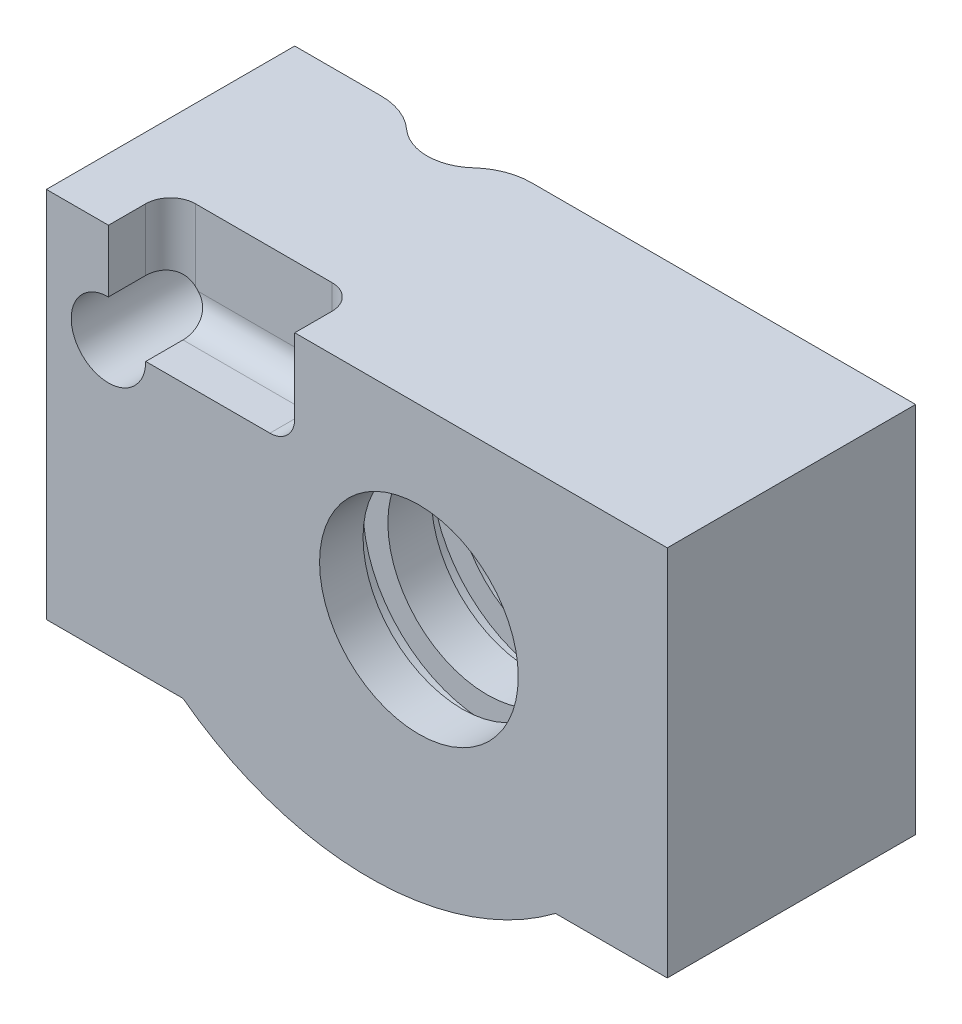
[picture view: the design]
ISO-10303-21;
HEADER;
FILE_DESCRIPTION(('STEP AP214'),'2;1');
FILE_NAME('part.step','',(''),(''),'','','');
FILE_SCHEMA(('AUTOMOTIVE_DESIGN { 1 0 10303 214 1 1 1 1 }'));
ENDSEC;
DATA;
#1=APPLICATION_CONTEXT('core data for automotive mechanical design processes');
#2=APPLICATION_PROTOCOL_DEFINITION('international standard','automotive_design',2000,#1);
#3=PRODUCT_CONTEXT('',#1,'mechanical');
#4=PRODUCT('Part','Part','',(#3));
#5=PRODUCT_RELATED_PRODUCT_CATEGORY('part','',(#4));
#6=PRODUCT_DEFINITION_FORMATION('','',#4);
#7=PRODUCT_DEFINITION_CONTEXT('part definition',#1,'design');
#8=PRODUCT_DEFINITION('design','',#6,#7);
#9=PRODUCT_DEFINITION_SHAPE('','',#8);
#10=(LENGTH_UNIT() NAMED_UNIT(*) SI_UNIT(.MILLI.,.METRE.));
#11=(NAMED_UNIT(*) PLANE_ANGLE_UNIT() SI_UNIT($,.RADIAN.));
#12=(NAMED_UNIT(*) SI_UNIT($,.STERADIAN.) SOLID_ANGLE_UNIT());
#13=UNCERTAINTY_MEASURE_WITH_UNIT(LENGTH_MEASURE(1.E-05),#10,'distance_accuracy_value','');
#14=(GEOMETRIC_REPRESENTATION_CONTEXT(3) GLOBAL_UNCERTAINTY_ASSIGNED_CONTEXT((#13)) GLOBAL_UNIT_ASSIGNED_CONTEXT((#10,
#11,#12)) REPRESENTATION_CONTEXT('',''));
#15=CARTESIAN_POINT('',(0.,0.,0.));
#16=DIRECTION('',(0.,0.,1.));
#17=DIRECTION('',(1.,0.,0.));
#18=AXIS2_PLACEMENT_3D('',#15,#16,#17);
#19=CARTESIAN_POINT('',(-15.,-3.,0.));
#20=DIRECTION('',(0.,0.,1.));
#21=DIRECTION('',(1.,0.,0.));
#22=AXIS2_PLACEMENT_3D('',#19,#20,#21);
#23=CYLINDRICAL_SURFACE('',#22,2.73470224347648);
#24=CARTESIAN_POINT('',(-14.3097315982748,-0.353846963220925,1.29981927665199));
#25=CARTESIAN_POINT('',(-14.2525353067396,-0.368760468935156,1.24781669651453));
#26=CARTESIAN_POINT('',(-14.1944120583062,-0.385909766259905,1.19743520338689));
#27=CARTESIAN_POINT('',(-14.076859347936,-0.425074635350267,1.10011331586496));
#28=CARTESIAN_POINT('',(-14.0174288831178,-0.44709406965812,1.05317569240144));
#29=CARTESIAN_POINT('',(-13.8977510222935,-0.496433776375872,0.962909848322));
#30=CARTESIAN_POINT('',(-13.8375019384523,-0.523767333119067,0.919591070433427));
#31=CARTESIAN_POINT('',(-13.7170788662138,-0.58396219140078,0.836898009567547));
#32=CARTESIAN_POINT('',(-13.6569048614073,-0.616821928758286,0.797522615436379));
#33=CARTESIAN_POINT('',(-13.5370757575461,-0.688431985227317,0.722618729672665));
#34=CARTESIAN_POINT('',(-13.4774254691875,-0.727214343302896,0.687113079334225));
#35=CARTESIAN_POINT('',(-13.3598545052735,-0.810545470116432,0.620250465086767));
#36=CARTESIAN_POINT('',(-13.3019337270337,-0.855093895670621,0.588893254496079));
#37=CARTESIAN_POINT('',(-13.18880539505,-0.949733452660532,0.530336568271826));
#38=CARTESIAN_POINT('',(-13.1335922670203,-0.999812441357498,0.503128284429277));
#39=CARTESIAN_POINT('',(-13.0265936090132,-1.10529180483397,0.452653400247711));
#40=CARTESIAN_POINT('',(-12.9748077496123,-1.16069166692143,0.429386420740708));
#41=CARTESIAN_POINT('',(-12.8344798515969,-1.32416998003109,0.368935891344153));
#42=CARTESIAN_POINT('',(-12.7507455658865,-1.43809325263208,0.336049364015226));
#43=CARTESIAN_POINT('',(-12.6010621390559,-1.67942623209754,0.280873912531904));
#44=CARTESIAN_POINT('',(-12.535127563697,-1.80684686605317,0.2585936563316));
#45=CARTESIAN_POINT('',(-12.4241609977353,-2.07050977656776,0.222859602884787));
#46=CARTESIAN_POINT('',(-12.3789786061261,-2.20668015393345,0.20934199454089));
#47=CARTESIAN_POINT('',(-12.3104350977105,-2.4848632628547,0.189382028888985));
#48=CARTESIAN_POINT('',(-12.2870707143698,-2.6268751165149,0.182938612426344));
#49=CARTESIAN_POINT('',(-12.2626192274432,-2.91648713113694,0.176200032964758));
#50=CARTESIAN_POINT('',(-12.2620956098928,-3.06413874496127,0.17606038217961));
#51=CARTESIAN_POINT('',(-12.2847754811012,-3.35748969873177,0.182302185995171));
#52=CARTESIAN_POINT('',(-12.3079824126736,-3.5031887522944,0.188684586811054));
#53=CARTESIAN_POINT('',(-12.3775659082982,-3.78947891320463,0.208914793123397));
#54=CARTESIAN_POINT('',(-12.4240989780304,-3.93002854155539,0.22281307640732));
#55=CARTESIAN_POINT('',(-12.5386456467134,-4.20080315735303,0.259753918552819));
#56=CARTESIAN_POINT('',(-12.6066570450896,-4.33102920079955,0.282795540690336));
#57=CARTESIAN_POINT('',(-12.7599982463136,-4.57525843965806,0.339612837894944));
#58=CARTESIAN_POINT('',(-12.8450321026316,-4.68948875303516,0.373210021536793));
#59=CARTESIAN_POINT('',(-13.029039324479,-4.90092889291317,0.453056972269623));
#60=CARTESIAN_POINT('',(-13.128003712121,-4.9981495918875,0.499298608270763));
#61=CARTESIAN_POINT('',(-13.332630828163,-5.17165682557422,0.604412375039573));
#62=CARTESIAN_POINT('',(-13.4380995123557,-5.2483550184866,0.662985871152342));
#63=CARTESIAN_POINT('',(-13.6526986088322,-5.38315984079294,0.793529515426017));
#64=CARTESIAN_POINT('',(-13.761832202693,-5.44124982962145,0.865511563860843));
#65=CARTESIAN_POINT('',(-13.9450508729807,-5.52436763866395,0.997554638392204));
#66=CARTESIAN_POINT('',(-14.0194593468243,-5.55405727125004,1.05433974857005));
#67=CARTESIAN_POINT('',(-14.1662950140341,-5.60568092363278,1.17319528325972));
#68=CARTESIAN_POINT('',(-14.2387280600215,-5.62764084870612,1.23524717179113));
#69=CARTESIAN_POINT('',(-14.3097315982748,-5.64615303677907,1.29981927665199));
#70=B_SPLINE_CURVE_WITH_KNOTS('',3,(#24,#25,#26,#27,#28,#29,#30,#31,#32,#33,#34,#35,#36,#37,#38,
#39,#40,#41,#42,#43,#44,#45,#46,#47,#48,#49,#50,#51,#52,#53,#54,#55,#56,#57,#58,#59,#60,#61,#62,
#63,#64,#65,#66,#67,#68,#69),.UNSPECIFIED.,.F.,.F.,(4,2,2,2,2,2,2,2,2,2,2,2,2,2,2,2,2,2,2,2,2,2,
4),(0.,0.236170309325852,0.472528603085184,0.709485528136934,0.946375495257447,1.18459557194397,
1.4228014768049,1.66049440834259,1.89816445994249,2.33134880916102,2.7648865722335,
3.19523067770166,3.62551034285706,4.06639923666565,4.50735210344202,4.95130393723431,
5.39521030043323,5.83198135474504,6.26847219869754,6.69540839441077,7.12272532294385,
7.41687160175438,7.71002247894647),.UNSPECIFIED.);
#71=CARTESIAN_POINT('',(-14.3097315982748,-0.353846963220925,1.29981927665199));
#72=VERTEX_POINT('',#71);
#73=CARTESIAN_POINT('',(-14.3097315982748,-5.64615303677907,1.29981927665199));
#74=VERTEX_POINT('',#73);
#75=EDGE_CURVE('E46',#72,#74,#70,.T.);
#76=ORIENTED_EDGE('',*,*,#75,.T.);
#77=CARTESIAN_POINT('',(-14.3097315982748,-0.353846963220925,1.29981927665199));
#78=CARTESIAN_POINT('',(-14.3670238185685,-0.338899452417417,1.35189784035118));
#79=CARTESIAN_POINT('',(-14.4260795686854,-0.325484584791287,1.40252226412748));
#80=CARTESIAN_POINT('',(-14.5475407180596,-0.302278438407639,1.50061271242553));
#81=CARTESIAN_POINT('',(-14.6099497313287,-0.292491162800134,1.54807520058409));
#82=CARTESIAN_POINT('',(-14.7382636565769,-0.277079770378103,1.63979796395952));
#83=CARTESIAN_POINT('',(-14.8041901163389,-0.271485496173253,1.68403329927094));
#84=CARTESIAN_POINT('',(-14.9387163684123,-0.265155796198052,1.76858375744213));
#85=CARTESIAN_POINT('',(-15.0073152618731,-0.264418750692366,1.80890018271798));
#86=CARTESIAN_POINT('',(-15.1472146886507,-0.26836018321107,1.8856014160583));
#87=CARTESIAN_POINT('',(-15.218531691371,-0.273079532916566,1.92195429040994));
#88=CARTESIAN_POINT('',(-15.362683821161,-0.288485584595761,1.99009257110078));
#89=CARTESIAN_POINT('',(-15.4355187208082,-0.299171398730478,2.02187865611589));
#90=CARTESIAN_POINT('',(-15.581631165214,-0.326836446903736,2.08058365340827));
#91=CARTESIAN_POINT('',(-15.6549059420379,-0.343791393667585,2.10752076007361));
#92=CARTESIAN_POINT('',(-15.8012337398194,-0.384203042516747,2.1566011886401));
#93=CARTESIAN_POINT('',(-15.8742867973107,-0.407658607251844,2.17874534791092));
#94=CARTESIAN_POINT('',(-16.0719221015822,-0.480615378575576,2.23267052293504));
#95=CARTESIAN_POINT('',(-16.1954508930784,-0.536668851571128,2.2597931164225));
#96=CARTESIAN_POINT('',(-16.4343972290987,-0.667678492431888,2.30135074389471));
#97=CARTESIAN_POINT('',(-16.5498061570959,-0.742654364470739,2.31577248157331));
#98=CARTESIAN_POINT('',(-16.7652483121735,-0.907079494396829,2.33420169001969));
#99=CARTESIAN_POINT('',(-16.8656354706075,-0.996034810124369,2.33850470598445));
#100=CARTESIAN_POINT('',(-17.052307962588,-1.18767056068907,2.34042384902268));
#101=CARTESIAN_POINT('',(-17.138593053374,-1.29035123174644,2.33803986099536));
#102=CARTESIAN_POINT('',(-17.3018640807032,-1.51639719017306,2.32917815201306));
#103=CARTESIAN_POINT('',(-17.377423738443,-1.64078044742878,2.32236777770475));
#104=CARTESIAN_POINT('',(-17.5078867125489,-1.89992549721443,2.30784480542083));
#105=CARTESIAN_POINT('',(-17.5627823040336,-2.03469114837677,2.30013187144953));
#106=CARTESIAN_POINT('',(-17.653119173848,-2.31945723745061,2.28627724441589));
#107=CARTESIAN_POINT('',(-17.6872327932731,-2.46988767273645,2.28025402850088));
#108=CARTESIAN_POINT('',(-17.7297161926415,-2.7744344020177,2.27261145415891));
#109=CARTESIAN_POINT('',(-17.7380900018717,-2.92855011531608,2.27099140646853));
#110=CARTESIAN_POINT('',(-17.7288914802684,-3.23424374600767,2.27270573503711));
#111=CARTESIAN_POINT('',(-17.7116082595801,-3.38583076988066,2.27598490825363));
#112=CARTESIAN_POINT('',(-17.6521593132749,-3.68392755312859,2.28626611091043));
#113=CARTESIAN_POINT('',(-17.6099885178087,-3.8304362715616,2.29326889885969));
#114=CARTESIAN_POINT('',(-17.5018278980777,-4.11474201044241,2.30844530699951));
#115=CARTESIAN_POINT('',(-17.4357767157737,-4.25251550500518,2.31662191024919));
#116=CARTESIAN_POINT('',(-17.2815973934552,-4.5152935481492,2.33049846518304));
#117=CARTESIAN_POINT('',(-17.1934659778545,-4.64029619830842,2.33619804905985));
#118=CARTESIAN_POINT('',(-16.9968725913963,-4.87473564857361,2.34088673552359));
#119=CARTESIAN_POINT('',(-16.8882856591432,-4.984069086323,2.33983320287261));
#120=CARTESIAN_POINT('',(-16.6546900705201,-5.18266926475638,2.32645108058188));
#121=CARTESIAN_POINT('',(-16.5296931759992,-5.27195025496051,2.314130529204));
#122=CARTESIAN_POINT('',(-16.2779209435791,-5.42185541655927,2.27586437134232));
#123=CARTESIAN_POINT('',(-16.1519511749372,-5.48410322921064,2.2509864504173));
#124=CARTESIAN_POINT('',(-15.8954077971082,-5.58765255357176,2.18640349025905));
#125=CARTESIAN_POINT('',(-15.7648385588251,-5.62897340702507,2.14671220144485));
#126=CARTESIAN_POINT('',(-15.5132922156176,-5.6890003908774,2.05537025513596));
#127=CARTESIAN_POINT('',(-15.3922670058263,-5.70905410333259,2.00471723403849));
#128=CARTESIAN_POINT('',(-15.1543870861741,-5.73296343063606,1.89089172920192));
#129=CARTESIAN_POINT('',(-15.0375407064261,-5.73678830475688,1.82769572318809));
#130=CARTESIAN_POINT('',(-14.813734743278,-5.730594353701,1.69183596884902));
#131=CARTESIAN_POINT('',(-14.7066064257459,-5.72090162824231,1.61943224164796));
#132=CARTESIAN_POINT('',(-14.5525686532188,-5.69834871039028,1.50419421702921));
#133=CARTESIAN_POINT('',(-14.5024275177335,-5.68952157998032,1.46476339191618));
#134=CARTESIAN_POINT('',(-14.4043866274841,-5.66952032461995,1.38382079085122));
#135=CARTESIAN_POINT('',(-14.3564856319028,-5.65834751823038,1.34231019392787));
#136=CARTESIAN_POINT('',(-14.3097315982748,-5.64615303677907,1.29981927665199));
#137=B_SPLINE_CURVE_WITH_KNOTS('',3,(#77,#78,#79,#80,#81,#82,#83,#84,#85,#86,#87,#88,#89,#90,
#91,#92,#93,#94,#95,#96,#97,#98,#99,#100,#101,#102,#103,#104,#105,#106,#107,#108,#109,#110,#111,
#112,#113,#114,#115,#116,#117,#118,#119,#120,#121,#122,#123,#124,#125,#126,#127,#128,#129,#130,
#131,#132,#133,#134,#135,#136),.UNSPECIFIED.,.F.,.F.,(4,2,2,2,2,2,2,2,2,2,2,2,2,2,2,2,2,2,2,2,2,
2,2,2,2,2,2,2,2,4),(0.,0.236560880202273,0.473382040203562,0.711873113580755,0.950284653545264,
1.19049367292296,1.43066695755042,1.66991937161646,1.90912995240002,2.32182800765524,
2.73495759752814,3.13586206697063,3.53677343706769,3.97196998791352,4.40732906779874,
4.86818550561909,5.32896979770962,5.78460110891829,6.24032526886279,6.69722878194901,
7.15420011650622,7.61405933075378,8.07359072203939,8.49935592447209,8.92472689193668,
9.32115139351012,9.71832646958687,10.106084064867,10.2991756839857,10.4921590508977),.UNSPECIFIED.);
#138=EDGE_CURVE('E52',#72,#74,#137,.T.);
#139=ORIENTED_EDGE('',*,*,#138,.F.);
#140=EDGE_LOOP('',(#76,#139));
#141=FACE_BOUND('',#140,.T.);
#142=CARTESIAN_POINT('',(-15.,-3.,5.));
#143=DIRECTION('',(0.,0.,1.));
#144=DIRECTION('',(1.,0.,0.));
#145=AXIS2_PLACEMENT_3D('',#142,#143,#144);
#146=CIRCLE('',#145,2.73470224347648);
#147=CARTESIAN_POINT('',(-12.2652977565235,-3.,5.));
#148=VERTEX_POINT('',#147);
#149=EDGE_CURVE('E11',#148,#148,#146,.F.);
#150=ORIENTED_EDGE('',*,*,#149,.F.);
#151=EDGE_LOOP('',(#150));
#152=FACE_BOUND('',#151,.T.);
#153=ADVANCED_FACE('F37',(#141,#152),#23,.F.);
#154=CARTESIAN_POINT('',(0.,0.,0.));
#155=DIRECTION('',(0.,0.,-1.));
#156=DIRECTION('',(-1.,0.,0.));
#157=AXIS2_PLACEMENT_3D('',#154,#155,#156);
#158=CYLINDRICAL_SURFACE('',#157,10.);
#159=CARTESIAN_POINT('',(0.,0.,14.5));
#160=DIRECTION('',(0.,0.,-1.));
#161=DIRECTION('',(-1.,0.,0.));
#162=AXIS2_PLACEMENT_3D('',#159,#160,#161);
#163=CIRCLE('',#162,10.);
#164=CARTESIAN_POINT('',(-10.,0.,14.5));
#165=VERTEX_POINT('',#164);
#166=EDGE_CURVE('E366',#165,#165,#163,.T.);
#167=ORIENTED_EDGE('',*,*,#166,.T.);
#168=EDGE_LOOP('',(#167));
#169=FACE_BOUND('',#168,.T.);
#170=CARTESIAN_POINT('',(0.,0.,16.5));
#171=DIRECTION('',(0.,0.,-1.));
#172=DIRECTION('',(-1.,0.,0.));
#173=AXIS2_PLACEMENT_3D('',#170,#171,#172);
#174=CIRCLE('',#173,10.);
#175=CARTESIAN_POINT('',(-10.,0.,16.5));
#176=VERTEX_POINT('',#175);
#177=EDGE_CURVE('E369',#176,#176,#174,.T.);
#178=ORIENTED_EDGE('',*,*,#177,.F.);
#179=EDGE_LOOP('',(#178));
#180=FACE_BOUND('',#179,.T.);
#181=CARTESIAN_POINT('',(0.,0.,16.));
#182=DIRECTION('',(0.,0.,-1.));
#183=DIRECTION('',(-1.,0.,0.));
#184=AXIS2_PLACEMENT_3D('',#181,#182,#183);
#185=CIRCLE('',#184,10.);
#186=CARTESIAN_POINT('',(3.65612152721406,9.30767293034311,16.));
#187=VERTEX_POINT('',#186);
#188=CARTESIAN_POINT('',(-3.65612152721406,9.30767293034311,16.));
#189=VERTEX_POINT('',#188);
#190=EDGE_CURVE('E480',#187,#189,#185,.F.);
#191=ORIENTED_EDGE('',*,*,#190,.F.);
#192=DIRECTION('',(0.,0.,-1.));
#193=VECTOR('',#192,1.);
#194=CARTESIAN_POINT('',(3.65612152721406,9.30767293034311,0.));
#195=LINE('',#194,#193);
#196=CARTESIAN_POINT('',(3.65612152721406,9.30767293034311,15.));
#197=VERTEX_POINT('',#196);
#198=EDGE_CURVE('E477',#197,#187,#195,.F.);
#199=ORIENTED_EDGE('',*,*,#198,.F.);
#200=CARTESIAN_POINT('',(0.,0.,15.));
#201=DIRECTION('',(0.,0.,1.));
#202=DIRECTION('',(1.,0.,0.));
#203=AXIS2_PLACEMENT_3D('',#200,#201,#202);
#204=CIRCLE('',#203,10.);
#205=CARTESIAN_POINT('',(-3.65612152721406,9.30767293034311,15.));
#206=VERTEX_POINT('',#205);
#207=EDGE_CURVE('E470',#206,#197,#204,.F.);
#208=ORIENTED_EDGE('',*,*,#207,.F.);
#209=DIRECTION('',(0.,0.,-1.));
#210=VECTOR('',#209,1.);
#211=CARTESIAN_POINT('',(-3.65612152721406,9.30767293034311,0.));
#212=LINE('',#211,#210);
#213=EDGE_CURVE('E472',#189,#206,#212,.T.);
#214=ORIENTED_EDGE('',*,*,#213,.F.);
#215=EDGE_LOOP('',(#191,#199,#208,#214));
#216=FACE_BOUND('',#215,.T.);
#217=ADVANCED_FACE('F267',(#169,#180,#216),#158,.F.);
#218=CARTESIAN_POINT('',(-4.,5.,0.));
#219=DIRECTION('',(0.,0.,1.));
#220=DIRECTION('',(1.,0.,0.));
#221=AXIS2_PLACEMENT_3D('',#218,#219,#220);
#222=PLANE('',#221);
#223=CARTESIAN_POINT('',(0.,0.,0.));
#224=DIRECTION('',(0.,0.,-1.));
#225=DIRECTION('',(-1.,0.,0.));
#226=AXIS2_PLACEMENT_3D('',#223,#224,#225);
#227=CIRCLE('',#226,8.);
#228=CARTESIAN_POINT('',(-8.,0.,0.));
#229=VERTEX_POINT('',#228);
#230=EDGE_CURVE('E336',#229,#229,#227,.T.);
#231=ORIENTED_EDGE('',*,*,#230,.F.);
#232=EDGE_LOOP('',(#231));
#233=FACE_BOUND('',#232,.T.);
#234=CARTESIAN_POINT('',(-4.,5.,0.));
#235=DIRECTION('',(0.,0.,1.));
#236=DIRECTION('',(1.,0.,0.));
#237=AXIS2_PLACEMENT_3D('',#234,#235,#236);
#238=CIRCLE('',#237,25.);
#239=CARTESIAN_POINT('',(-10.9468960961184,-19.0154249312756,0.));
#240=VERTEX_POINT('',#239);
#241=CARTESIAN_POINT('',(11.,-15.,0.));
#242=VERTEX_POINT('',#241);
#243=EDGE_CURVE('E418',#240,#242,#238,.T.);
#244=ORIENTED_EDGE('',*,*,#243,.F.);
#245=DIRECTION('',(0.,1.,0.));
#246=VECTOR('',#245,1.);
#247=CARTESIAN_POINT('',(-10.9468960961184,5.,0.));
#248=LINE('',#247,#246);
#249=CARTESIAN_POINT('',(-10.9468960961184,15.,0.));
#250=VERTEX_POINT('',#249);
#251=EDGE_CURVE('E395',#240,#250,#248,.T.);
#252=ORIENTED_EDGE('',*,*,#251,.T.);
#253=DIRECTION('',(-1.,0.,0.));
#254=VECTOR('',#253,1.);
#255=CARTESIAN_POINT('',(-30.,15.,0.));
#256=LINE('',#255,#254);
#257=CARTESIAN_POINT('',(20.,15.,0.));
#258=VERTEX_POINT('',#257);
#259=EDGE_CURVE('E412',#258,#250,#256,.T.);
#260=ORIENTED_EDGE('',*,*,#259,.F.);
#261=DIRECTION('',(0.,1.,0.));
#262=VECTOR('',#261,1.);
#263=CARTESIAN_POINT('',(20.,15.,0.));
#264=LINE('',#263,#262);
#265=CARTESIAN_POINT('',(20.,-15.,0.));
#266=VERTEX_POINT('',#265);
#267=EDGE_CURVE('E422',#266,#258,#264,.T.);
#268=ORIENTED_EDGE('',*,*,#267,.F.);
#269=DIRECTION('',(1.,0.,0.));
#270=VECTOR('',#269,1.);
#271=CARTESIAN_POINT('',(11.,-15.,0.));
#272=LINE('',#271,#270);
#273=EDGE_CURVE('E419',#242,#266,#272,.T.);
#274=ORIENTED_EDGE('',*,*,#273,.F.);
#275=EDGE_LOOP('',(#244,#252,#260,#268,#274));
#276=FACE_BOUND('',#275,.T.);
#277=ADVANCED_FACE('F415',(#233,#276),#222,.F.);
#278=CARTESIAN_POINT('',(-30.,15.,20.));
#279=DIRECTION('',(1.,0.,0.));
#280=DIRECTION('',(0.,1.,0.));
#281=AXIS2_PLACEMENT_3D('',#278,#279,#280);
#282=PLANE('',#281);
#283=DIRECTION('',(0.,-1.,0.));
#284=VECTOR('',#283,1.);
#285=CARTESIAN_POINT('',(-30.,15.,0.));
#286=LINE('',#285,#284);
#287=CARTESIAN_POINT('',(-30.,15.,0.));
#288=VERTEX_POINT('',#287);
#289=CARTESIAN_POINT('',(-30.,-15.,0.));
#290=VERTEX_POINT('',#289);
#291=EDGE_CURVE('E242',#288,#290,#286,.T.);
#292=ORIENTED_EDGE('',*,*,#291,.T.);
#293=DIRECTION('',(0.,0.,-1.));
#294=VECTOR('',#293,1.);
#295=CARTESIAN_POINT('',(-30.,-15.,20.));
#296=LINE('',#295,#294);
#297=CARTESIAN_POINT('',(-30.,-15.,20.));
#298=VERTEX_POINT('',#297);
#299=EDGE_CURVE('E391',#298,#290,#296,.T.);
#300=ORIENTED_EDGE('',*,*,#299,.F.);
#301=DIRECTION('',(0.,-1.,0.));
#302=VECTOR('',#301,1.);
#303=CARTESIAN_POINT('',(-30.,15.,20.));
#304=LINE('',#303,#302);
#305=CARTESIAN_POINT('',(-30.,15.,20.));
#306=VERTEX_POINT('',#305);
#307=EDGE_CURVE('E245',#306,#298,#304,.T.);
#308=ORIENTED_EDGE('',*,*,#307,.F.);
#309=DIRECTION('',(0.,0.,-1.));
#310=VECTOR('',#309,1.);
#311=CARTESIAN_POINT('',(-30.,15.,20.));
#312=LINE('',#311,#310);
#313=EDGE_CURVE('E430',#306,#288,#312,.T.);
#314=ORIENTED_EDGE('',*,*,#313,.T.);
#315=EDGE_LOOP('',(#292,#300,#308,#314));
#316=FACE_BOUND('',#315,.T.);
#317=ADVANCED_FACE('F457',(#316),#282,.F.);
#318=CARTESIAN_POINT('',(-30.,-15.,20.));
#319=DIRECTION('',(0.,1.,0.));
#320=DIRECTION('',(0.,0.,1.));
#321=AXIS2_PLACEMENT_3D('',#318,#319,#320);
#322=PLANE('',#321);
#323=DIRECTION('',(1.,0.,0.));
#324=VECTOR('',#323,1.);
#325=CARTESIAN_POINT('',(-30.,-15.,0.));
#326=LINE('',#325,#324);
#327=CARTESIAN_POINT('',(-23.0531039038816,-15.,0.));
#328=VERTEX_POINT('',#327);
#329=EDGE_CURVE('E420',#290,#328,#326,.T.);
#330=ORIENTED_EDGE('',*,*,#329,.T.);
#331=CARTESIAN_POINT('',(-23.0531039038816,-15.,5.));
#332=DIRECTION('',(0.,1.,0.));
#333=DIRECTION('',(0.,0.,1.));
#334=AXIS2_PLACEMENT_3D('',#331,#332,#333);
#335=CIRCLE('',#334,5.);
#336=CARTESIAN_POINT('',(-19.6902684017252,-15.,1.29981927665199));
#337=VERTEX_POINT('',#336);
#338=EDGE_CURVE('E387',#328,#337,#335,.F.);
#339=ORIENTED_EDGE('',*,*,#338,.T.);
#340=CARTESIAN_POINT('',(-17.,-15.,-1.66032530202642));
#341=DIRECTION('',(0.,1.,0.));
#342=DIRECTION('',(0.,0.,1.));
#343=AXIS2_PLACEMENT_3D('',#340,#341,#342);
#344=CIRCLE('',#343,4.);
#345=CARTESIAN_POINT('',(-19.,-15.,1.80377631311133));
#346=VERTEX_POINT('',#345);
#347=EDGE_CURVE('E243',#337,#346,#344,.T.);
#348=ORIENTED_EDGE('',*,*,#347,.T.);
#349=DIRECTION('',(0.,0.,-1.));
#350=VECTOR('',#349,1.);
#351=CARTESIAN_POINT('',(-19.,-15.,20.));
#352=LINE('',#351,#350);
#353=CARTESIAN_POINT('',(-19.,-15.,20.));
#354=VERTEX_POINT('',#353);
#355=EDGE_CURVE('E384',#354,#346,#352,.T.);
#356=ORIENTED_EDGE('',*,*,#355,.F.);
#357=DIRECTION('',(1.,0.,0.));
#358=VECTOR('',#357,1.);
#359=CARTESIAN_POINT('',(-30.,-15.,20.));
#360=LINE('',#359,#358);
#361=EDGE_CURVE('E449',#298,#354,#360,.T.);
#362=ORIENTED_EDGE('',*,*,#361,.F.);
#363=ORIENTED_EDGE('',*,*,#299,.T.);
#364=EDGE_LOOP('',(#330,#339,#348,#356,#362,#363));
#365=FACE_BOUND('',#364,.T.);
#366=ADVANCED_FACE('F230',(#365),#322,.F.);
#367=CARTESIAN_POINT('',(-4.,5.,20.));
#368=DIRECTION('',(0.,0.,-1.));
#369=DIRECTION('',(-1.,0.,0.));
#370=AXIS2_PLACEMENT_3D('',#367,#368,#369);
#371=CYLINDRICAL_SURFACE('',#370,25.);
#372=CARTESIAN_POINT('',(-19.,-15.,1.80377631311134));
#373=CARTESIAN_POINT('',(-18.8766514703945,-15.092531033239,1.87496960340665));
#374=CARTESIAN_POINT('',(-18.7499284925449,-15.1857713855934,1.93937151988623));
#375=CARTESIAN_POINT('',(-18.4905979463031,-15.3727248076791,2.05427814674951));
#376=CARTESIAN_POINT('',(-18.3579886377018,-15.4664380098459,2.10477871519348));
#377=CARTESIAN_POINT('',(-18.0871607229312,-15.6537939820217,2.191738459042));
#378=CARTESIAN_POINT('',(-17.9489177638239,-15.7474341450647,2.22812744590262));
#379=CARTESIAN_POINT('',(-17.6684245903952,-15.9332856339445,2.28602914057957));
#380=CARTESIAN_POINT('',(-17.5261748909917,-16.0254971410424,2.30754375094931));
#381=CARTESIAN_POINT('',(-17.2473858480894,-16.2021780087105,2.33432278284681));
#382=CARTESIAN_POINT('',(-17.1110167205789,-16.2867797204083,2.3404856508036));
#383=CARTESIAN_POINT('',(-16.836738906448,-16.4532948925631,2.33869315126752));
#384=CARTESIAN_POINT('',(-16.6988303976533,-16.5352086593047,2.33073939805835));
#385=CARTESIAN_POINT('',(-16.4229333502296,-16.6955325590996,2.30025769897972));
#386=CARTESIAN_POINT('',(-16.2849454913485,-16.7739492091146,2.27775818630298));
#387=CARTESIAN_POINT('',(-16.010012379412,-16.926794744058,2.21778154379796));
#388=CARTESIAN_POINT('',(-15.873066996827,-17.0012241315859,2.18030630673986));
#389=CARTESIAN_POINT('',(-15.6141808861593,-17.1388866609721,2.09418933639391));
#390=CARTESIAN_POINT('',(-15.4920111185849,-17.202521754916,2.0468783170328));
#391=CARTESIAN_POINT('',(-15.2511730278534,-17.3255320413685,1.93953276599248));
#392=CARTESIAN_POINT('',(-15.1325040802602,-17.3849079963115,1.87950051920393));
#393=CARTESIAN_POINT('',(-14.9000796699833,-17.4990006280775,1.74676245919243));
#394=CARTESIAN_POINT('',(-14.7863247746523,-17.5537167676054,1.67405518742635));
#395=CARTESIAN_POINT('',(-14.5652885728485,-17.6581025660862,1.5162466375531));
#396=CARTESIAN_POINT('',(-14.4580058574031,-17.7077733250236,1.43114807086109));
#397=CARTESIAN_POINT('',(-14.2657805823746,-17.7952476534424,1.26168046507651));
#398=CARTESIAN_POINT('',(-14.1798010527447,-17.8337422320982,1.1788403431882));
#399=CARTESIAN_POINT('',(-14.0148134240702,-17.9065851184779,1.00482544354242));
#400=CARTESIAN_POINT('',(-13.9358040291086,-17.9409341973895,0.913652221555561));
#401=CARTESIAN_POINT('',(-13.7859206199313,-18.0052688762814,0.72384790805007));
#402=CARTESIAN_POINT('',(-13.7150254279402,-18.0352658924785,0.625237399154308));
#403=CARTESIAN_POINT('',(-13.5820659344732,-18.0908900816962,0.421149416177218));
#404=CARTESIAN_POINT('',(-13.519994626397,-18.1165207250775,0.315677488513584));
#405=CARTESIAN_POINT('',(-13.4447966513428,-18.1472717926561,0.173253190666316));
#406=CARTESIAN_POINT('',(-13.4273235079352,-18.1543928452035,0.138971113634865));
#407=CARTESIAN_POINT('',(-13.3933587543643,-18.1681925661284,0.0698820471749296));
#408=CARTESIAN_POINT('',(-13.3768661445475,-18.1748716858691,0.035075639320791));
#409=CARTESIAN_POINT('',(-13.3608627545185,-18.1813340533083,0.));
#410=B_SPLINE_CURVE_WITH_KNOTS('',3,(#372,#373,#374,#375,#376,#377,#378,#379,#380,#381,#382,
#383,#384,#385,#386,#387,#388,#389,#390,#391,#392,#393,#394,#395,#396,#397,#398,#399,#400,#401,
#402,#403,#404,#405,#406,#407,#408,#409),.UNSPECIFIED.,.F.,.F.,(4,2,2,2,2,2,2,2,2,2,2,2,2,2,2,2,
2,2,4),(0.,0.509334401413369,1.01882039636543,1.53080894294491,2.04273198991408,
2.52390640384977,3.00502579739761,3.48520755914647,3.96532865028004,4.40164585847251,
4.83788476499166,5.27417390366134,5.71036771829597,6.08619501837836,6.46195229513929,
6.83670534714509,7.21115914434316,7.32854097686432,7.44580101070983),.UNSPECIFIED.);
#411=CARTESIAN_POINT('',(-14.3097315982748,-17.7751933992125,1.299819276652));
#412=VERTEX_POINT('',#411);
#413=EDGE_CURVE('E235',#346,#412,#410,.T.);
#414=ORIENTED_EDGE('',*,*,#413,.T.);
#415=CARTESIAN_POINT('',(-14.3097315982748,-17.7751933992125,1.29981927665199));
#416=CARTESIAN_POINT('',(-14.1978751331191,-17.8258366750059,1.19815632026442));
#417=CARTESIAN_POINT('',(-14.0816547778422,-17.8774454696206,1.10179760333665));
#418=CARTESIAN_POINT('',(-13.8413583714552,-17.9818343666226,0.920201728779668));
#419=CARTESIAN_POINT('',(-13.7172839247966,-18.0346142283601,0.834962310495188));
#420=CARTESIAN_POINT('',(-13.4657670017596,-18.1390857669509,0.678356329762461));
#421=CARTESIAN_POINT('',(-13.338523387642,-18.1907652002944,0.606661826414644));
#422=CARTESIAN_POINT('',(-13.0781893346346,-18.2939063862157,0.474639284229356));
#423=CARTESIAN_POINT('',(-12.9450989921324,-18.3453681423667,0.414311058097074));
#424=CARTESIAN_POINT('',(-12.6652657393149,-18.4507335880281,0.301984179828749));
#425=CARTESIAN_POINT('',(-12.5181924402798,-18.5045849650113,0.250757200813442));
#426=CARTESIAN_POINT('',(-12.2193957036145,-18.6107325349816,0.162125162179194));
#427=CARTESIAN_POINT('',(-12.0676723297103,-18.6630287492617,0.12471991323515));
#428=CARTESIAN_POINT('',(-11.7558575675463,-18.7670874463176,0.0632397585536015));
#429=CARTESIAN_POINT('',(-11.5956530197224,-18.8187815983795,0.0396203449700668));
#430=CARTESIAN_POINT('',(-11.2727716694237,-18.9193577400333,0.00798840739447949));
#431=CARTESIAN_POINT('',(-11.1100938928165,-18.9682385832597,-1.77976235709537E-05));
#432=CARTESIAN_POINT('',(-10.9468960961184,-19.0154249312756,0.));
#433=B_SPLINE_CURVE_WITH_KNOTS('',3,(#415,#416,#417,#418,#419,#420,#421,#422,#423,#424,#425,
#426,#427,#428,#429,#430,#431,#432),.UNSPECIFIED.,.F.,.F.,(4,2,2,2,2,2,2,2,4),(0.,
0.478065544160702,0.956033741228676,1.42028420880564,1.8845270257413,2.37823435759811,
2.87193492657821,3.381138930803,3.89054897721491),.UNSPECIFIED.);
#434=EDGE_CURVE('E205',#412,#240,#433,.T.);
#435=ORIENTED_EDGE('',*,*,#434,.T.);
#436=ORIENTED_EDGE('',*,*,#243,.T.);
#437=DIRECTION('',(0.,0.,-1.));
#438=VECTOR('',#437,1.);
#439=CARTESIAN_POINT('',(11.,-15.,20.));
#440=LINE('',#439,#438);
#441=CARTESIAN_POINT('',(11.,-15.,20.));
#442=VERTEX_POINT('',#441);
#443=EDGE_CURVE('E392',#442,#242,#440,.T.);
#444=ORIENTED_EDGE('',*,*,#443,.F.);
#445=CARTESIAN_POINT('',(-4.,5.,20.));
#446=DIRECTION('',(0.,0.,1.));
#447=DIRECTION('',(1.,0.,0.));
#448=AXIS2_PLACEMENT_3D('',#445,#446,#447);
#449=CIRCLE('',#448,25.);
#450=EDGE_CURVE('E390',#354,#442,#449,.T.);
#451=ORIENTED_EDGE('',*,*,#450,.F.);
#452=ORIENTED_EDGE('',*,*,#355,.T.);
#453=EDGE_LOOP('',(#414,#435,#436,#444,#451,#452));
#454=FACE_BOUND('',#453,.T.);
#455=ADVANCED_FACE('F224',(#454),#371,.T.);
#456=CARTESIAN_POINT('',(11.,-15.,20.));
#457=DIRECTION('',(0.,1.,0.));
#458=DIRECTION('',(0.,0.,1.));
#459=AXIS2_PLACEMENT_3D('',#456,#457,#458);
#460=PLANE('',#459);
#461=ORIENTED_EDGE('',*,*,#273,.T.);
#462=DIRECTION('',(0.,0.,-1.));
#463=VECTOR('',#462,1.);
#464=CARTESIAN_POINT('',(20.,-15.,20.));
#465=LINE('',#464,#463);
#466=CARTESIAN_POINT('',(20.,-15.,20.));
#467=VERTEX_POINT('',#466);
#468=EDGE_CURVE('E398',#467,#266,#465,.T.);
#469=ORIENTED_EDGE('',*,*,#468,.F.);
#470=DIRECTION('',(1.,0.,0.));
#471=VECTOR('',#470,1.);
#472=CARTESIAN_POINT('',(11.,-15.,20.));
#473=LINE('',#472,#471);
#474=EDGE_CURVE('E444',#442,#467,#473,.T.);
#475=ORIENTED_EDGE('',*,*,#474,.F.);
#476=ORIENTED_EDGE('',*,*,#443,.T.);
#477=EDGE_LOOP('',(#461,#469,#475,#476));
#478=FACE_BOUND('',#477,.T.);
#479=ADVANCED_FACE('F229',(#478),#460,.F.);
#480=CARTESIAN_POINT('',(20.,15.,20.));
#481=DIRECTION('',(-1.,0.,0.));
#482=DIRECTION('',(0.,-1.,0.));
#483=AXIS2_PLACEMENT_3D('',#480,#481,#482);
#484=PLANE('',#483);
#485=ORIENTED_EDGE('',*,*,#267,.T.);
#486=DIRECTION('',(0.,0.,-1.));
#487=VECTOR('',#486,1.);
#488=CARTESIAN_POINT('',(20.,15.,20.));
#489=LINE('',#488,#487);
#490=CARTESIAN_POINT('',(20.,15.,20.));
#491=VERTEX_POINT('',#490);
#492=EDGE_CURVE('E433',#491,#258,#489,.T.);
#493=ORIENTED_EDGE('',*,*,#492,.F.);
#494=DIRECTION('',(0.,1.,0.));
#495=VECTOR('',#494,1.);
#496=CARTESIAN_POINT('',(20.,15.,20.));
#497=LINE('',#496,#495);
#498=EDGE_CURVE('E441',#467,#491,#497,.T.);
#499=ORIENTED_EDGE('',*,*,#498,.F.);
#500=ORIENTED_EDGE('',*,*,#468,.T.);
#501=EDGE_LOOP('',(#485,#493,#499,#500));
#502=FACE_BOUND('',#501,.T.);
#503=ADVANCED_FACE('F439',(#502),#484,.F.);
#504=CARTESIAN_POINT('',(-30.,15.,20.));
#505=DIRECTION('',(0.,-1.,0.));
#506=DIRECTION('',(0.,0.,-1.));
#507=AXIS2_PLACEMENT_3D('',#504,#505,#506);
#508=PLANE('',#507);
#509=DIRECTION('',(-1.,0.,0.));
#510=VECTOR('',#509,1.);
#511=CARTESIAN_POINT('',(-30.,15.,20.));
#512=LINE('',#511,#510);
#513=CARTESIAN_POINT('',(-25.,15.,20.));
#514=VERTEX_POINT('',#513);
#515=EDGE_CURVE('E447',#514,#306,#512,.T.);
#516=ORIENTED_EDGE('',*,*,#515,.F.);
#517=DIRECTION('',(0.,0.,1.));
#518=VECTOR('',#517,1.);
#519=CARTESIAN_POINT('',(-25.,15.,15.));
#520=LINE('',#519,#518);
#521=CARTESIAN_POINT('',(-25.,15.,17.));
#522=VERTEX_POINT('',#521);
#523=EDGE_CURVE('E327',#522,#514,#520,.T.);
#524=ORIENTED_EDGE('',*,*,#523,.F.);
#525=CARTESIAN_POINT('',(-23.,15.,17.));
#526=DIRECTION('',(0.,-1.,0.));
#527=DIRECTION('',(0.,0.,-1.));
#528=AXIS2_PLACEMENT_3D('',#525,#526,#527);
#529=CIRCLE('',#528,2.);
#530=CARTESIAN_POINT('',(-23.,15.,15.));
#531=VERTEX_POINT('',#530);
#532=EDGE_CURVE('E505',#522,#531,#529,.T.);
#533=ORIENTED_EDGE('',*,*,#532,.T.);
#534=DIRECTION('',(-1.,0.,0.));
#535=VECTOR('',#534,1.);
#536=CARTESIAN_POINT('',(-25.,15.,15.));
#537=LINE('',#536,#535);
#538=CARTESIAN_POINT('',(-12.,15.,15.));
#539=VERTEX_POINT('',#538);
#540=EDGE_CURVE('E315',#539,#531,#537,.T.);
#541=ORIENTED_EDGE('',*,*,#540,.F.);
#542=CARTESIAN_POINT('',(-12.,15.,17.));
#543=DIRECTION('',(0.,-1.,0.));
#544=DIRECTION('',(0.,0.,-1.));
#545=AXIS2_PLACEMENT_3D('',#542,#543,#544);
#546=CIRCLE('',#545,2.);
#547=CARTESIAN_POINT('',(-10.,15.,17.));
#548=VERTEX_POINT('',#547);
#549=EDGE_CURVE('E282',#539,#548,#546,.T.);
#550=ORIENTED_EDGE('',*,*,#549,.T.);
#551=DIRECTION('',(0.,0.,1.));
#552=VECTOR('',#551,1.);
#553=CARTESIAN_POINT('',(-10.,15.,15.));
#554=LINE('',#553,#552);
#555=CARTESIAN_POINT('',(-10.,15.,20.));
#556=VERTEX_POINT('',#555);
#557=EDGE_CURVE('E318',#548,#556,#554,.T.);
#558=ORIENTED_EDGE('',*,*,#557,.T.);
#559=EDGE_CURVE('E434',#491,#556,#512,.T.);
#560=ORIENTED_EDGE('',*,*,#559,.F.);
#561=ORIENTED_EDGE('',*,*,#492,.T.);
#562=ORIENTED_EDGE('',*,*,#259,.T.);
#563=CARTESIAN_POINT('',(-10.9468960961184,15.,5.));
#564=DIRECTION('',(0.,-1.,0.));
#565=DIRECTION('',(0.,0.,-1.));
#566=AXIS2_PLACEMENT_3D('',#563,#564,#565);
#567=CIRCLE('',#566,5.);
#568=CARTESIAN_POINT('',(-14.3097315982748,15.,1.29981927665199));
#569=VERTEX_POINT('',#568);
#570=EDGE_CURVE('E208',#250,#569,#567,.F.);
#571=ORIENTED_EDGE('',*,*,#570,.T.);
#572=CARTESIAN_POINT('',(-17.,15.,-1.66032530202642));
#573=DIRECTION('',(0.,1.,0.));
#574=DIRECTION('',(0.,0.,1.));
#575=AXIS2_PLACEMENT_3D('',#572,#573,#574);
#576=CIRCLE('',#575,4.);
#577=CARTESIAN_POINT('',(-19.6902684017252,15.,1.29981927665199));
#578=VERTEX_POINT('',#577);
#579=EDGE_CURVE('E377',#578,#569,#576,.T.);
#580=ORIENTED_EDGE('',*,*,#579,.F.);
#581=CARTESIAN_POINT('',(-23.0531039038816,15.,5.));
#582=DIRECTION('',(0.,-1.,0.));
#583=DIRECTION('',(0.,0.,-1.));
#584=AXIS2_PLACEMENT_3D('',#581,#582,#583);
#585=CIRCLE('',#584,5.);
#586=CARTESIAN_POINT('',(-23.0531039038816,15.,0.));
#587=VERTEX_POINT('',#586);
#588=EDGE_CURVE('E404',#578,#587,#585,.F.);
#589=ORIENTED_EDGE('',*,*,#588,.T.);
#590=EDGE_CURVE('E428',#587,#288,#256,.T.);
#591=ORIENTED_EDGE('',*,*,#590,.T.);
#592=ORIENTED_EDGE('',*,*,#313,.F.);
#593=EDGE_LOOP('',(#516,#524,#533,#541,#550,#558,#560,#561,#562,#571,#580,#589,#591,#592));
#594=FACE_BOUND('',#593,.T.);
#595=ADVANCED_FACE('F408',(#594),#508,.F.);
#596=CARTESIAN_POINT('',(-4.,5.,20.));
#597=DIRECTION('',(0.,0.,1.));
#598=DIRECTION('',(1.,0.,0.));
#599=AXIS2_PLACEMENT_3D('',#596,#597,#598);
#600=PLANE('',#599);
#601=CARTESIAN_POINT('',(-25.,7.,20.));
#602=DIRECTION('',(0.,0.,1.));
#603=DIRECTION('',(1.,0.,0.));
#604=AXIS2_PLACEMENT_3D('',#601,#602,#603);
#605=CIRCLE('',#604,3.);
#606=CARTESIAN_POINT('',(-25.,10.,20.));
#607=VERTEX_POINT('',#606);
#608=CARTESIAN_POINT('',(-22.,7.,20.));
#609=VERTEX_POINT('',#608);
#610=EDGE_CURVE('E200',#607,#609,#605,.T.);
#611=ORIENTED_EDGE('',*,*,#610,.F.);
#612=DIRECTION('',(0.,-1.,0.));
#613=VECTOR('',#612,1.);
#614=CARTESIAN_POINT('',(-25.,15.,20.));
#615=LINE('',#614,#613);
#616=EDGE_CURVE('E320',#514,#607,#615,.T.);
#617=ORIENTED_EDGE('',*,*,#616,.F.);
#618=ORIENTED_EDGE('',*,*,#515,.T.);
#619=ORIENTED_EDGE('',*,*,#307,.T.);
#620=ORIENTED_EDGE('',*,*,#361,.T.);
#621=ORIENTED_EDGE('',*,*,#450,.T.);
#622=ORIENTED_EDGE('',*,*,#474,.T.);
#623=ORIENTED_EDGE('',*,*,#498,.T.);
#624=ORIENTED_EDGE('',*,*,#559,.T.);
#625=DIRECTION('',(0.,1.,0.));
#626=VECTOR('',#625,1.);
#627=CARTESIAN_POINT('',(-10.,15.,20.));
#628=LINE('',#627,#626);
#629=CARTESIAN_POINT('',(-10.,9.,20.));
#630=VERTEX_POINT('',#629);
#631=EDGE_CURVE('E319',#630,#556,#628,.T.);
#632=ORIENTED_EDGE('',*,*,#631,.F.);
#633=CARTESIAN_POINT('',(-12.,9.,20.));
#634=DIRECTION('',(0.,0.,1.));
#635=DIRECTION('',(1.,0.,0.));
#636=AXIS2_PLACEMENT_3D('',#633,#634,#635);
#637=CIRCLE('',#636,2.);
#638=CARTESIAN_POINT('',(-12.,7.,20.));
#639=VERTEX_POINT('',#638);
#640=EDGE_CURVE('E502',#630,#639,#637,.F.);
#641=ORIENTED_EDGE('',*,*,#640,.T.);
#642=DIRECTION('',(1.,0.,0.));
#643=VECTOR('',#642,1.);
#644=CARTESIAN_POINT('',(-25.,7.,20.));
#645=LINE('',#644,#643);
#646=EDGE_CURVE('E323',#609,#639,#645,.T.);
#647=ORIENTED_EDGE('',*,*,#646,.F.);
#648=EDGE_LOOP('',(#611,#617,#618,#619,#620,#621,#622,#623,#624,#632,#641,#647));
#649=FACE_BOUND('',#648,.T.);
#650=CARTESIAN_POINT('',(0.,0.,20.));
#651=DIRECTION('',(0.,0.,-1.));
#652=DIRECTION('',(-1.,0.,0.));
#653=AXIS2_PLACEMENT_3D('',#650,#651,#652);
#654=CIRCLE('',#653,8.);
#655=CARTESIAN_POINT('',(-8.,0.,20.));
#656=VERTEX_POINT('',#655);
#657=EDGE_CURVE('E375',#656,#656,#654,.T.);
#658=ORIENTED_EDGE('',*,*,#657,.T.);
#659=EDGE_LOOP('',(#658));
#660=FACE_BOUND('',#659,.T.);
#661=ADVANCED_FACE('F254',(#649,#660),#600,.T.);
#662=DIRECTION('',(0.,1.,0.));
#663=VECTOR('',#662,1.);
#664=CARTESIAN_POINT('',(-23.0531039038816,5.,0.));
#665=LINE('',#664,#663);
#666=CARTESIAN_POINT('',(-23.0531039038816,9.28245385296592,0.));
#667=VERTEX_POINT('',#666);
#668=EDGE_CURVE('E219',#587,#667,#665,.F.);
#669=ORIENTED_EDGE('',*,*,#668,.T.);
#670=CARTESIAN_POINT('',(-25.,7.,0.));
#671=DIRECTION('',(0.,0.,1.));
#672=DIRECTION('',(1.,0.,0.));
#673=AXIS2_PLACEMENT_3D('',#670,#671,#672);
#674=CIRCLE('',#673,3.);
#675=CARTESIAN_POINT('',(-23.0531039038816,4.71754614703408,0.));
#676=VERTEX_POINT('',#675);
#677=EDGE_CURVE('E59',#667,#676,#674,.T.);
#678=ORIENTED_EDGE('',*,*,#677,.T.);
#679=EDGE_CURVE('E218',#676,#328,#665,.F.);
#680=ORIENTED_EDGE('',*,*,#679,.T.);
#681=ORIENTED_EDGE('',*,*,#329,.F.);
#682=ORIENTED_EDGE('',*,*,#291,.F.);
#683=ORIENTED_EDGE('',*,*,#590,.F.);
#684=EDGE_LOOP('',(#669,#678,#680,#681,#682,#683));
#685=FACE_BOUND('',#684,.T.);
#686=ADVANCED_FACE('F251',(#685),#222,.F.);
#687=CARTESIAN_POINT('',(-17.,-20.,-1.66032530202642));
#688=DIRECTION('',(0.,1.,0.));
#689=DIRECTION('',(0.,0.,1.));
#690=AXIS2_PLACEMENT_3D('',#687,#688,#689);
#691=CYLINDRICAL_SURFACE('',#690,4.);
#692=DIRECTION('',(0.,1.,0.));
#693=VECTOR('',#692,1.);
#694=CARTESIAN_POINT('',(-14.3097315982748,-20.,1.29981927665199));
#695=LINE('',#694,#693);
#696=EDGE_CURVE('E199',#569,#72,#695,.F.);
#697=ORIENTED_EDGE('',*,*,#696,.T.);
#698=ORIENTED_EDGE('',*,*,#138,.T.);
#699=EDGE_CURVE('E196',#74,#412,#695,.F.);
#700=ORIENTED_EDGE('',*,*,#699,.T.);
#701=ORIENTED_EDGE('',*,*,#413,.F.);
#702=ORIENTED_EDGE('',*,*,#347,.F.);
#703=DIRECTION('',(0.,1.,0.));
#704=VECTOR('',#703,1.);
#705=CARTESIAN_POINT('',(-19.6902684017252,-20.,1.29981927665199));
#706=LINE('',#705,#704);
#707=EDGE_CURVE('E206',#337,#578,#706,.T.);
#708=ORIENTED_EDGE('',*,*,#707,.T.);
#709=ORIENTED_EDGE('',*,*,#579,.T.);
#710=EDGE_LOOP('',(#697,#698,#700,#701,#702,#708,#709));
#711=FACE_BOUND('',#710,.T.);
#712=ADVANCED_FACE('F194',(#711),#691,.F.);
#713=CARTESIAN_POINT('',(-10.9468960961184,-20.,5.));
#714=DIRECTION('',(0.,1.,0.));
#715=DIRECTION('',(0.,0.,1.));
#716=AXIS2_PLACEMENT_3D('',#713,#714,#715);
#717=CYLINDRICAL_SURFACE('',#716,5.);
#718=ORIENTED_EDGE('',*,*,#75,.F.);
#719=ORIENTED_EDGE('',*,*,#696,.F.);
#720=ORIENTED_EDGE('',*,*,#570,.F.);
#721=ORIENTED_EDGE('',*,*,#251,.F.);
#722=ORIENTED_EDGE('',*,*,#434,.F.);
#723=ORIENTED_EDGE('',*,*,#699,.F.);
#724=EDGE_LOOP('',(#718,#719,#720,#721,#722,#723));
#725=FACE_BOUND('',#724,.T.);
#726=ADVANCED_FACE('F203',(#725),#717,.T.);
#727=CARTESIAN_POINT('',(-23.0531039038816,-20.,5.));
#728=DIRECTION('',(0.,1.,0.));
#729=DIRECTION('',(0.,0.,1.));
#730=AXIS2_PLACEMENT_3D('',#727,#728,#729);
#731=CYLINDRICAL_SURFACE('',#730,5.);
#732=CARTESIAN_POINT('',(-23.0531039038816,9.28245385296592,0.));
#733=CARTESIAN_POINT('',(-22.9893216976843,9.22806071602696,-1.68794127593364E-06));
#734=CARTESIAN_POINT('',(-22.9278456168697,9.17099290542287,0.00122046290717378));
#735=CARTESIAN_POINT('',(-22.8099310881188,9.05197436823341,0.00556891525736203));
#736=CARTESIAN_POINT('',(-22.7534908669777,8.99002537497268,0.00869454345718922));
#737=CARTESIAN_POINT('',(-22.6460712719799,8.86172377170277,0.0163041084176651));
#738=CARTESIAN_POINT('',(-22.5950875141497,8.79537476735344,0.0207869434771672));
#739=CARTESIAN_POINT('',(-22.4988663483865,8.65871140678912,0.0305778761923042));
#740=CARTESIAN_POINT('',(-22.4536293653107,8.58839675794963,0.0358860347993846));
#741=CARTESIAN_POINT('',(-22.3270489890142,8.37227492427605,0.0522620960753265));
#742=CARTESIAN_POINT('',(-22.2546797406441,8.22110257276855,0.0637955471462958));
#743=CARTESIAN_POINT('',(-22.1360800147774,7.90878565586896,0.0844412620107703));
#744=CARTESIAN_POINT('',(-22.0898442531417,7.74764311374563,0.0935540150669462));
#745=CARTESIAN_POINT('',(-22.0245197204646,7.41824290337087,0.106825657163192));
#746=CARTESIAN_POINT('',(-22.0056695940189,7.24993569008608,0.110940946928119));
#747=CARTESIAN_POINT('',(-21.996530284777,6.91252570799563,0.112906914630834));
#748=CARTESIAN_POINT('',(-22.0062384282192,6.74342301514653,0.110758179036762));
#749=CARTESIAN_POINT('',(-22.0533635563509,6.41296360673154,0.100911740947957));
#750=CARTESIAN_POINT('',(-22.0901922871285,6.25151875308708,0.0933319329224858));
#751=CARTESIAN_POINT('',(-22.1898174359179,5.93693184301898,0.0748319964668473));
#752=CARTESIAN_POINT('',(-22.2526332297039,5.78379607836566,0.0639093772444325));
#753=CARTESIAN_POINT('',(-22.4038144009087,5.48738416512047,0.0417388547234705));
#754=CARTESIAN_POINT('',(-22.4926047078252,5.34432553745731,0.0304885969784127));
#755=CARTESIAN_POINT('',(-22.6928882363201,5.07509876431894,0.0119873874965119));
#756=CARTESIAN_POINT('',(-22.8043244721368,4.94888951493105,0.00472656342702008));
#757=CARTESIAN_POINT('',(-22.9461120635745,4.81313568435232,0.00110156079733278));
#758=CARTESIAN_POINT('',(-22.9671353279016,4.79358003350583,0.000693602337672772));
#759=CARTESIAN_POINT('',(-23.0097167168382,4.75509650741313,0.000143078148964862));
#760=CARTESIAN_POINT('',(-23.0312743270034,4.73616806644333,2.6649178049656E-07));
#761=CARTESIAN_POINT('',(-23.0531039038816,4.71754614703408,0.));
#762=B_SPLINE_CURVE_WITH_KNOTS('',3,(#732,#733,#734,#735,#736,#737,#738,#739,#740,#741,#742,
#743,#744,#745,#746,#747,#748,#749,#750,#751,#752,#753,#754,#755,#756,#757,#758,#759,#760,#761),
.UNSPECIFIED.,.F.,.F.,(4,2,2,2,2,2,2,2,2,2,2,2,2,2,4),(0.,0.251366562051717,0.502644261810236,
0.753718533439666,1.00481135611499,1.50627281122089,2.00763283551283,2.51333614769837,
3.01899211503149,3.51399177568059,4.00936117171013,4.51333695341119,5.0160599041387,
5.10220060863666,5.18826137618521),.UNSPECIFIED.);
#763=EDGE_CURVE('E306',#667,#676,#762,.T.);
#764=ORIENTED_EDGE('',*,*,#763,.F.);
#765=ORIENTED_EDGE('',*,*,#668,.F.);
#766=ORIENTED_EDGE('',*,*,#588,.F.);
#767=ORIENTED_EDGE('',*,*,#707,.F.);
#768=ORIENTED_EDGE('',*,*,#338,.F.);
#769=ORIENTED_EDGE('',*,*,#679,.F.);
#770=EDGE_LOOP('',(#764,#765,#766,#767,#768,#769));
#771=FACE_BOUND('',#770,.T.);
#772=ADVANCED_FACE('F301',(#771),#731,.T.);
#773=CARTESIAN_POINT('',(0.,0.,0.));
#774=DIRECTION('',(0.,0.,-1.));
#775=DIRECTION('',(-1.,0.,0.));
#776=AXIS2_PLACEMENT_3D('',#773,#774,#775);
#777=CYLINDRICAL_SURFACE('',#776,8.);
#778=ORIENTED_EDGE('',*,*,#657,.F.);
#779=EDGE_LOOP('',(#778));
#780=FACE_BOUND('',#779,.T.);
#781=CARTESIAN_POINT('',(0.,0.,16.5));
#782=DIRECTION('',(0.,0.,-1.));
#783=DIRECTION('',(-1.,0.,0.));
#784=AXIS2_PLACEMENT_3D('',#781,#782,#783);
#785=CIRCLE('',#784,8.);
#786=CARTESIAN_POINT('',(-8.,0.,16.5));
#787=VERTEX_POINT('',#786);
#788=EDGE_CURVE('E372',#787,#787,#785,.T.);
#789=ORIENTED_EDGE('',*,*,#788,.T.);
#790=EDGE_LOOP('',(#789));
#791=FACE_BOUND('',#790,.T.);
#792=ADVANCED_FACE('F252',(#780,#791),#777,.F.);
#793=CARTESIAN_POINT('',(-10.,0.,16.5));
#794=DIRECTION('',(0.,0.,1.));
#795=DIRECTION('',(1.,0.,0.));
#796=AXIS2_PLACEMENT_3D('',#793,#794,#795);
#797=PLANE('',#796);
#798=ORIENTED_EDGE('',*,*,#788,.F.);
#799=EDGE_LOOP('',(#798));
#800=FACE_BOUND('',#799,.T.);
#801=ORIENTED_EDGE('',*,*,#177,.T.);
#802=EDGE_LOOP('',(#801));
#803=FACE_BOUND('',#802,.T.);
#804=ADVANCED_FACE('F647',(#800,#803),#797,.F.);
#805=CARTESIAN_POINT('',(-10.,0.,14.5));
#806=DIRECTION('',(0.,0.,-1.));
#807=DIRECTION('',(-1.,0.,0.));
#808=AXIS2_PLACEMENT_3D('',#805,#806,#807);
#809=PLANE('',#808);
#810=ORIENTED_EDGE('',*,*,#166,.F.);
#811=EDGE_LOOP('',(#810));
#812=FACE_BOUND('',#811,.T.);
#813=CARTESIAN_POINT('',(0.,0.,14.5));
#814=DIRECTION('',(0.,0.,-1.));
#815=DIRECTION('',(-1.,0.,0.));
#816=AXIS2_PLACEMENT_3D('',#813,#814,#815);
#817=CIRCLE('',#816,8.);
#818=CARTESIAN_POINT('',(-8.,0.,14.5));
#819=VERTEX_POINT('',#818);
#820=EDGE_CURVE('E363',#819,#819,#817,.T.);
#821=ORIENTED_EDGE('',*,*,#820,.T.);
#822=EDGE_LOOP('',(#821));
#823=FACE_BOUND('',#822,.T.);
#824=ADVANCED_FACE('F657',(#812,#823),#809,.F.);
#825=CARTESIAN_POINT('',(0.,0.,0.));
#826=DIRECTION('',(0.,0.,-1.));
#827=DIRECTION('',(-1.,0.,0.));
#828=AXIS2_PLACEMENT_3D('',#825,#826,#827);
#829=CYLINDRICAL_SURFACE('',#828,8.);
#830=ORIENTED_EDGE('',*,*,#820,.F.);
#831=EDGE_LOOP('',(#830));
#832=FACE_BOUND('',#831,.T.);
#833=CARTESIAN_POINT('',(0.,0.,11.));
#834=DIRECTION('',(0.,0.,-1.));
#835=DIRECTION('',(-1.,0.,0.));
#836=AXIS2_PLACEMENT_3D('',#833,#834,#835);
#837=CIRCLE('',#836,8.);
#838=CARTESIAN_POINT('',(-8.,0.,11.));
#839=VERTEX_POINT('',#838);
#840=EDGE_CURVE('E360',#839,#839,#837,.T.);
#841=ORIENTED_EDGE('',*,*,#840,.T.);
#842=EDGE_LOOP('',(#841));
#843=FACE_BOUND('',#842,.T.);
#844=ADVANCED_FACE('F665',(#832,#843),#829,.F.);
#845=CARTESIAN_POINT('',(-10.,0.,11.));
#846=DIRECTION('',(0.,0.,1.));
#847=DIRECTION('',(1.,0.,0.));
#848=AXIS2_PLACEMENT_3D('',#845,#846,#847);
#849=PLANE('',#848);
#850=ORIENTED_EDGE('',*,*,#840,.F.);
#851=EDGE_LOOP('',(#850));
#852=FACE_BOUND('',#851,.T.);
#853=CARTESIAN_POINT('',(0.,0.,11.));
#854=DIRECTION('',(0.,0.,-1.));
#855=DIRECTION('',(-1.,0.,0.));
#856=AXIS2_PLACEMENT_3D('',#853,#854,#855);
#857=CIRCLE('',#856,10.);
#858=CARTESIAN_POINT('',(-10.,0.,11.));
#859=VERTEX_POINT('',#858);
#860=EDGE_CURVE('E357',#859,#859,#857,.T.);
#861=ORIENTED_EDGE('',*,*,#860,.T.);
#862=EDGE_LOOP('',(#861));
#863=FACE_BOUND('',#862,.T.);
#864=ADVANCED_FACE('F674',(#852,#863),#849,.F.);
#865=CARTESIAN_POINT('',(0.,0.,0.));
#866=DIRECTION('',(0.,0.,-1.));
#867=DIRECTION('',(-1.,0.,0.));
#868=AXIS2_PLACEMENT_3D('',#865,#866,#867);
#869=CYLINDRICAL_SURFACE('',#868,10.);
#870=ORIENTED_EDGE('',*,*,#860,.F.);
#871=EDGE_LOOP('',(#870));
#872=FACE_BOUND('',#871,.T.);
#873=CARTESIAN_POINT('',(0.,0.,9.));
#874=DIRECTION('',(0.,0.,-1.));
#875=DIRECTION('',(-1.,0.,0.));
#876=AXIS2_PLACEMENT_3D('',#873,#874,#875);
#877=CIRCLE('',#876,10.);
#878=CARTESIAN_POINT('',(-10.,0.,9.));
#879=VERTEX_POINT('',#878);
#880=EDGE_CURVE('E354',#879,#879,#877,.T.);
#881=ORIENTED_EDGE('',*,*,#880,.T.);
#882=EDGE_LOOP('',(#881));
#883=FACE_BOUND('',#882,.T.);
#884=ADVANCED_FACE('F684',(#872,#883),#869,.F.);
#885=CARTESIAN_POINT('',(-10.,0.,9.));
#886=DIRECTION('',(0.,0.,-1.));
#887=DIRECTION('',(-1.,0.,0.));
#888=AXIS2_PLACEMENT_3D('',#885,#886,#887);
#889=PLANE('',#888);
#890=ORIENTED_EDGE('',*,*,#880,.F.);
#891=EDGE_LOOP('',(#890));
#892=FACE_BOUND('',#891,.T.);
#893=CARTESIAN_POINT('',(0.,0.,9.));
#894=DIRECTION('',(0.,0.,-1.));
#895=DIRECTION('',(-1.,0.,0.));
#896=AXIS2_PLACEMENT_3D('',#893,#894,#895);
#897=CIRCLE('',#896,8.);
#898=CARTESIAN_POINT('',(-8.,0.,9.));
#899=VERTEX_POINT('',#898);
#900=EDGE_CURVE('E351',#899,#899,#897,.T.);
#901=ORIENTED_EDGE('',*,*,#900,.T.);
#902=EDGE_LOOP('',(#901));
#903=FACE_BOUND('',#902,.T.);
#904=ADVANCED_FACE('F693',(#892,#903),#889,.F.);
#905=CARTESIAN_POINT('',(0.,0.,0.));
#906=DIRECTION('',(0.,0.,-1.));
#907=DIRECTION('',(-1.,0.,0.));
#908=AXIS2_PLACEMENT_3D('',#905,#906,#907);
#909=CYLINDRICAL_SURFACE('',#908,8.);
#910=ORIENTED_EDGE('',*,*,#900,.F.);
#911=EDGE_LOOP('',(#910));
#912=FACE_BOUND('',#911,.T.);
#913=CARTESIAN_POINT('',(0.,0.,5.5));
#914=DIRECTION('',(0.,0.,-1.));
#915=DIRECTION('',(-1.,0.,0.));
#916=AXIS2_PLACEMENT_3D('',#913,#914,#915);
#917=CIRCLE('',#916,8.);
#918=CARTESIAN_POINT('',(-8.,0.,5.5));
#919=VERTEX_POINT('',#918);
#920=EDGE_CURVE('E348',#919,#919,#917,.T.);
#921=ORIENTED_EDGE('',*,*,#920,.T.);
#922=EDGE_LOOP('',(#921));
#923=FACE_BOUND('',#922,.T.);
#924=ADVANCED_FACE('F702',(#912,#923),#909,.F.);
#925=CARTESIAN_POINT('',(-10.,0.,5.5));
#926=DIRECTION('',(0.,0.,1.));
#927=DIRECTION('',(1.,0.,0.));
#928=AXIS2_PLACEMENT_3D('',#925,#926,#927);
#929=PLANE('',#928);
#930=ORIENTED_EDGE('',*,*,#920,.F.);
#931=EDGE_LOOP('',(#930));
#932=FACE_BOUND('',#931,.T.);
#933=CARTESIAN_POINT('',(0.,0.,5.5));
#934=DIRECTION('',(0.,0.,-1.));
#935=DIRECTION('',(-1.,0.,0.));
#936=AXIS2_PLACEMENT_3D('',#933,#934,#935);
#937=CIRCLE('',#936,10.);
#938=CARTESIAN_POINT('',(-10.,0.,5.5));
#939=VERTEX_POINT('',#938);
#940=EDGE_CURVE('E345',#939,#939,#937,.T.);
#941=ORIENTED_EDGE('',*,*,#940,.T.);
#942=EDGE_LOOP('',(#941));
#943=FACE_BOUND('',#942,.T.);
#944=ADVANCED_FACE('F711',(#932,#943),#929,.F.);
#945=CARTESIAN_POINT('',(0.,0.,0.));
#946=DIRECTION('',(0.,0.,-1.));
#947=DIRECTION('',(-1.,0.,0.));
#948=AXIS2_PLACEMENT_3D('',#945,#946,#947);
#949=CYLINDRICAL_SURFACE('',#948,10.);
#950=ORIENTED_EDGE('',*,*,#940,.F.);
#951=EDGE_LOOP('',(#950));
#952=FACE_BOUND('',#951,.T.);
#953=CARTESIAN_POINT('',(0.,0.,3.5));
#954=DIRECTION('',(0.,0.,-1.));
#955=DIRECTION('',(-1.,0.,0.));
#956=AXIS2_PLACEMENT_3D('',#953,#954,#955);
#957=CIRCLE('',#956,10.);
#958=CARTESIAN_POINT('',(-10.,0.,3.5));
#959=VERTEX_POINT('',#958);
#960=EDGE_CURVE('E342',#959,#959,#957,.T.);
#961=ORIENTED_EDGE('',*,*,#960,.T.);
#962=EDGE_LOOP('',(#961));
#963=FACE_BOUND('',#962,.T.);
#964=ADVANCED_FACE('F720',(#952,#963),#949,.F.);
#965=CARTESIAN_POINT('',(-10.,0.,3.5));
#966=DIRECTION('',(0.,0.,-1.));
#967=DIRECTION('',(-1.,0.,0.));
#968=AXIS2_PLACEMENT_3D('',#965,#966,#967);
#969=PLANE('',#968);
#970=ORIENTED_EDGE('',*,*,#960,.F.);
#971=EDGE_LOOP('',(#970));
#972=FACE_BOUND('',#971,.T.);
#973=CARTESIAN_POINT('',(0.,0.,3.5));
#974=DIRECTION('',(0.,0.,-1.));
#975=DIRECTION('',(-1.,0.,0.));
#976=AXIS2_PLACEMENT_3D('',#973,#974,#975);
#977=CIRCLE('',#976,8.);
#978=CARTESIAN_POINT('',(-8.,0.,3.5));
#979=VERTEX_POINT('',#978);
#980=EDGE_CURVE('E339',#979,#979,#977,.T.);
#981=ORIENTED_EDGE('',*,*,#980,.T.);
#982=EDGE_LOOP('',(#981));
#983=FACE_BOUND('',#982,.T.);
#984=ADVANCED_FACE('F729',(#972,#983),#969,.F.);
#985=CARTESIAN_POINT('',(0.,0.,0.));
#986=DIRECTION('',(0.,0.,-1.));
#987=DIRECTION('',(-1.,0.,0.));
#988=AXIS2_PLACEMENT_3D('',#985,#986,#987);
#989=CYLINDRICAL_SURFACE('',#988,8.);
#990=ORIENTED_EDGE('',*,*,#980,.F.);
#991=EDGE_LOOP('',(#990));
#992=FACE_BOUND('',#991,.T.);
#993=ORIENTED_EDGE('',*,*,#230,.T.);
#994=EDGE_LOOP('',(#993));
#995=FACE_BOUND('',#994,.T.);
#996=ADVANCED_FACE('F738',(#992,#995),#989,.F.);
#997=CARTESIAN_POINT('',(20.,10.6872453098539,16.));
#998=DIRECTION('',(0.,0.,-1.));
#999=DIRECTION('',(-1.,0.,0.));
#1000=AXIS2_PLACEMENT_3D('',#997,#998,#999);
#1001=PLANE('',#1000);
#1002=DIRECTION('',(-1.,0.,0.));
#1003=VECTOR('',#1002,1.);
#1004=CARTESIAN_POINT('',(20.,9.30767293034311,16.));
#1005=LINE('',#1004,#1003);
#1006=EDGE_CURVE('E333',#187,#189,#1005,.T.);
#1007=ORIENTED_EDGE('',*,*,#1006,.F.);
#1008=ORIENTED_EDGE('',*,*,#190,.T.);
#1009=EDGE_LOOP('',(#1007,#1008));
#1010=FACE_BOUND('',#1009,.T.);
#1011=ADVANCED_FACE('F747',(#1010),#1001,.F.);
#1012=CARTESIAN_POINT('',(20.,9.30767293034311,16.));
#1013=DIRECTION('',(0.,1.,0.));
#1014=DIRECTION('',(0.,0.,1.));
#1015=AXIS2_PLACEMENT_3D('',#1012,#1013,#1014);
#1016=PLANE('',#1015);
#1017=DIRECTION('',(-1.,0.,0.));
#1018=VECTOR('',#1017,1.);
#1019=CARTESIAN_POINT('',(20.,9.30767293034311,15.));
#1020=LINE('',#1019,#1018);
#1021=EDGE_CURVE('E329',#197,#206,#1020,.T.);
#1022=ORIENTED_EDGE('',*,*,#1021,.F.);
#1023=ORIENTED_EDGE('',*,*,#198,.T.);
#1024=ORIENTED_EDGE('',*,*,#1006,.T.);
#1025=ORIENTED_EDGE('',*,*,#213,.T.);
#1026=EDGE_LOOP('',(#1022,#1023,#1024,#1025));
#1027=FACE_BOUND('',#1026,.T.);
#1028=ADVANCED_FACE('F756',(#1027),#1016,.F.);
#1029=CARTESIAN_POINT('',(20.,10.6872453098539,15.));
#1030=DIRECTION('',(0.,0.,1.));
#1031=DIRECTION('',(1.,0.,0.));
#1032=AXIS2_PLACEMENT_3D('',#1029,#1030,#1031);
#1033=PLANE('',#1032);
#1034=ORIENTED_EDGE('',*,*,#1021,.T.);
#1035=ORIENTED_EDGE('',*,*,#207,.T.);
#1036=EDGE_LOOP('',(#1034,#1035));
#1037=FACE_BOUND('',#1036,.T.);
#1038=ADVANCED_FACE('F764',(#1037),#1033,.F.);
#1039=CARTESIAN_POINT('',(-25.,15.,15.));
#1040=DIRECTION('',(-1.,0.,0.));
#1041=DIRECTION('',(0.,-1.,0.));
#1042=AXIS2_PLACEMENT_3D('',#1039,#1040,#1041);
#1043=PLANE('',#1042);
#1044=ORIENTED_EDGE('',*,*,#616,.T.);
#1045=DIRECTION('',(0.,0.,1.));
#1046=VECTOR('',#1045,1.);
#1047=CARTESIAN_POINT('',(-25.,10.,0.));
#1048=LINE('',#1047,#1046);
#1049=CARTESIAN_POINT('',(-25.,10.,17.));
#1050=VERTEX_POINT('',#1049);
#1051=EDGE_CURVE('E313',#607,#1050,#1048,.F.);
#1052=ORIENTED_EDGE('',*,*,#1051,.T.);
#1053=DIRECTION('',(0.,-1.,0.));
#1054=VECTOR('',#1053,1.);
#1055=CARTESIAN_POINT('',(-25.,15.,17.));
#1056=LINE('',#1055,#1054);
#1057=EDGE_CURVE('E493',#1050,#522,#1056,.F.);
#1058=ORIENTED_EDGE('',*,*,#1057,.T.);
#1059=ORIENTED_EDGE('',*,*,#523,.T.);
#1060=EDGE_LOOP('',(#1044,#1052,#1058,#1059));
#1061=FACE_BOUND('',#1060,.T.);
#1062=ADVANCED_FACE('F547',(#1061),#1043,.F.);
#1063=CARTESIAN_POINT('',(-10.,15.,15.));
#1064=DIRECTION('',(1.,0.,0.));
#1065=DIRECTION('',(0.,1.,0.));
#1066=AXIS2_PLACEMENT_3D('',#1063,#1064,#1065);
#1067=PLANE('',#1066);
#1068=DIRECTION('',(0.,1.,0.));
#1069=VECTOR('',#1068,1.);
#1070=CARTESIAN_POINT('',(-10.,15.,17.));
#1071=LINE('',#1070,#1069);
#1072=CARTESIAN_POINT('',(-10.,9.,17.));
#1073=VERTEX_POINT('',#1072);
#1074=EDGE_CURVE('E483',#548,#1073,#1071,.F.);
#1075=ORIENTED_EDGE('',*,*,#1074,.T.);
#1076=DIRECTION('',(0.,0.,1.));
#1077=VECTOR('',#1076,1.);
#1078=CARTESIAN_POINT('',(-10.,9.,20.));
#1079=LINE('',#1078,#1077);
#1080=EDGE_CURVE('E485',#1073,#630,#1079,.T.);
#1081=ORIENTED_EDGE('',*,*,#1080,.T.);
#1082=ORIENTED_EDGE('',*,*,#631,.T.);
#1083=ORIENTED_EDGE('',*,*,#557,.F.);
#1084=EDGE_LOOP('',(#1075,#1081,#1082,#1083));
#1085=FACE_BOUND('',#1084,.T.);
#1086=ADVANCED_FACE('F521',(#1085),#1067,.F.);
#1087=CARTESIAN_POINT('',(-25.,7.,15.));
#1088=DIRECTION('',(0.,-1.,0.));
#1089=DIRECTION('',(0.,0.,-1.));
#1090=AXIS2_PLACEMENT_3D('',#1087,#1088,#1089);
#1091=PLANE('',#1090);
#1092=DIRECTION('',(1.,0.,0.));
#1093=VECTOR('',#1092,1.);
#1094=CARTESIAN_POINT('',(-25.,7.,17.));
#1095=LINE('',#1094,#1093);
#1096=CARTESIAN_POINT('',(-12.,7.,17.));
#1097=VERTEX_POINT('',#1096);
#1098=CARTESIAN_POINT('',(-22.,7.,17.));
#1099=VERTEX_POINT('',#1098);
#1100=EDGE_CURVE('E488',#1097,#1099,#1095,.F.);
#1101=ORIENTED_EDGE('',*,*,#1100,.T.);
#1102=DIRECTION('',(0.,0.,1.));
#1103=VECTOR('',#1102,1.);
#1104=CARTESIAN_POINT('',(-22.,7.,0.));
#1105=LINE('',#1104,#1103);
#1106=EDGE_CURVE('E540',#1099,#609,#1105,.T.);
#1107=ORIENTED_EDGE('',*,*,#1106,.T.);
#1108=ORIENTED_EDGE('',*,*,#646,.T.);
#1109=DIRECTION('',(0.,0.,1.));
#1110=VECTOR('',#1109,1.);
#1111=CARTESIAN_POINT('',(-12.,7.,15.));
#1112=LINE('',#1111,#1110);
#1113=EDGE_CURVE('E491',#639,#1097,#1112,.F.);
#1114=ORIENTED_EDGE('',*,*,#1113,.T.);
#1115=EDGE_LOOP('',(#1101,#1107,#1108,#1114));
#1116=FACE_BOUND('',#1115,.T.);
#1117=ADVANCED_FACE('F544',(#1116),#1091,.F.);
#1118=CARTESIAN_POINT('',(0.,0.,15.));
#1119=DIRECTION('',(0.,0.,1.));
#1120=DIRECTION('',(1.,0.,0.));
#1121=AXIS2_PLACEMENT_3D('',#1118,#1119,#1120);
#1122=PLANE('',#1121);
#1123=CARTESIAN_POINT('',(-25.,7.,15.));
#1124=DIRECTION('',(0.,0.,1.));
#1125=DIRECTION('',(1.,0.,0.));
#1126=AXIS2_PLACEMENT_3D('',#1123,#1124,#1125);
#1127=CIRCLE('',#1126,3.);
#1128=CARTESIAN_POINT('',(-22.7639320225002,9.,15.));
#1129=VERTEX_POINT('',#1128);
#1130=CARTESIAN_POINT('',(-23.,9.23606797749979,15.));
#1131=VERTEX_POINT('',#1130);
#1132=EDGE_CURVE('E538',#1129,#1131,#1127,.T.);
#1133=ORIENTED_EDGE('',*,*,#1132,.F.);
#1134=DIRECTION('',(1.,0.,0.));
#1135=VECTOR('',#1134,1.);
#1136=CARTESIAN_POINT('',(0.,9.,15.));
#1137=LINE('',#1136,#1135);
#1138=CARTESIAN_POINT('',(-12.,9.,15.));
#1139=VERTEX_POINT('',#1138);
#1140=EDGE_CURVE('E497',#1129,#1139,#1137,.T.);
#1141=ORIENTED_EDGE('',*,*,#1140,.T.);
#1142=DIRECTION('',(0.,1.,0.));
#1143=VECTOR('',#1142,1.);
#1144=CARTESIAN_POINT('',(-12.,0.,15.));
#1145=LINE('',#1144,#1143);
#1146=EDGE_CURVE('E495',#1139,#539,#1145,.T.);
#1147=ORIENTED_EDGE('',*,*,#1146,.T.);
#1148=ORIENTED_EDGE('',*,*,#540,.T.);
#1149=DIRECTION('',(0.,-1.,0.));
#1150=VECTOR('',#1149,1.);
#1151=CARTESIAN_POINT('',(-23.,0.,15.));
#1152=LINE('',#1151,#1150);
#1153=EDGE_CURVE('E499',#531,#1131,#1152,.T.);
#1154=ORIENTED_EDGE('',*,*,#1153,.T.);
#1155=EDGE_LOOP('',(#1133,#1141,#1147,#1148,#1154));
#1156=FACE_BOUND('',#1155,.T.);
#1157=ADVANCED_FACE('F531',(#1156),#1122,.T.);
#1158=CARTESIAN_POINT('',(-23.,0.,17.));
#1159=DIRECTION('',(0.,-1.,0.));
#1160=DIRECTION('',(1.,0.,0.));
#1161=AXIS2_PLACEMENT_3D('',#1158,#1159,#1160);
#1162=CYLINDRICAL_SURFACE('',#1161,2.);
#1163=ORIENTED_EDGE('',*,*,#1057,.F.);
#1164=CARTESIAN_POINT('',(-25.,10.,17.));
#1165=CARTESIAN_POINT('',(-25.000005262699,9.99998843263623,16.9440031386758));
#1166=CARTESIAN_POINT('',(-24.9976482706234,9.99999970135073,16.8880088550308));
#1167=CARTESIAN_POINT('',(-24.9882505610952,9.99998372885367,16.7764162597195));
#1168=CARTESIAN_POINT('',(-24.9812099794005,9.99995648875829,16.7208179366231));
#1169=CARTESIAN_POINT('',(-24.9624826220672,9.99977929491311,16.6103856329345));
#1170=CARTESIAN_POINT('',(-24.9507942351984,9.99962929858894,16.5555519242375));
#1171=CARTESIAN_POINT('',(-24.922866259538,9.9990404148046,16.4470743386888));
#1172=CARTESIAN_POINT('',(-24.9066267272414,9.99860153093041,16.3934304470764));
#1173=CARTESIAN_POINT('',(-24.8512030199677,9.99653979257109,16.23477289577));
#1174=CARTESIAN_POINT('',(-24.8053108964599,9.99417194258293,16.1320167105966));
#1175=CARTESIAN_POINT('',(-24.6970989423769,9.98515946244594,15.9358535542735));
#1176=CARTESIAN_POINT('',(-24.6347868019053,9.97851683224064,15.8424422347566));
#1177=CARTESIAN_POINT('',(-24.4971125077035,9.95835130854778,15.6693432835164));
#1178=CARTESIAN_POINT('',(-24.422008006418,9.94495560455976,15.5894371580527));
#1179=CARTESIAN_POINT('',(-24.2610550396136,9.908733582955,15.4438857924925));
#1180=CARTESIAN_POINT('',(-24.1752142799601,9.88591400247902,15.3782304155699));
#1181=CARTESIAN_POINT('',(-24.0030142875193,9.83083256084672,15.2668668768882));
#1182=CARTESIAN_POINT('',(-23.9170976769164,9.79932898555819,15.2200965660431));
#1183=CARTESIAN_POINT('',(-23.7432605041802,9.72571184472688,15.1407811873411));
#1184=CARTESIAN_POINT('',(-23.6553395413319,9.68359614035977,15.1082389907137));
#1185=CARTESIAN_POINT('',(-23.483069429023,9.59004592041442,15.0571778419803));
#1186=CARTESIAN_POINT('',(-23.3986841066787,9.53883009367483,15.0383737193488));
#1187=CARTESIAN_POINT('',(-23.2343524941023,9.42741169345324,15.0120358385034));
#1188=CARTESIAN_POINT('',(-23.1544025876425,9.36721659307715,15.0044927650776));
#1189=CARTESIAN_POINT('',(-23.0513648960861,9.28122996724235,15.000485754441));
#1190=CARTESIAN_POINT('',(-23.0254772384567,9.25886317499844,14.9999976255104));
#1191=CARTESIAN_POINT('',(-23.,9.23606797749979,15.));
#1192=B_SPLINE_CURVE_WITH_KNOTS('',3,(#1164,#1165,#1166,#1167,#1168,#1169,#1170,#1171,#1172,
#1173,#1174,#1175,#1176,#1177,#1178,#1179,#1180,#1181,#1182,#1183,#1184,#1185,#1186,#1187,#1188,
#1189,#1190,#1191),.UNSPECIFIED.,.F.,.F.,(4,2,2,2,2,2,2,2,2,2,2,2,2,4),(0.,0.167936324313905,
0.335867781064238,0.503857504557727,0.671845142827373,1.00777038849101,1.34353858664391,
1.67320672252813,2.00263958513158,2.30939066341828,2.61620361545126,2.9164513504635,
3.21645058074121,3.31905049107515),.UNSPECIFIED.);
#1193=EDGE_CURVE('E537',#1050,#1131,#1192,.T.);
#1194=ORIENTED_EDGE('',*,*,#1193,.T.);
#1195=ORIENTED_EDGE('',*,*,#1153,.F.);
#1196=ORIENTED_EDGE('',*,*,#532,.F.);
#1197=EDGE_LOOP('',(#1163,#1194,#1195,#1196));
#1198=FACE_BOUND('',#1197,.T.);
#1199=ADVANCED_FACE('F39',(#1198),#1162,.F.);
#1200=CARTESIAN_POINT('',(0.,9.,17.));
#1201=DIRECTION('',(1.,0.,0.));
#1202=DIRECTION('',(0.,0.,-1.));
#1203=AXIS2_PLACEMENT_3D('',#1200,#1201,#1202);
#1204=CYLINDRICAL_SURFACE('',#1203,2.);
#1205=ORIENTED_EDGE('',*,*,#1140,.F.);
#1206=CARTESIAN_POINT('',(-22.7639320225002,9.,15.));
#1207=CARTESIAN_POINT('',(-22.7271145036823,8.95884908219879,14.9999975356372));
#1208=CARTESIAN_POINT('',(-22.6914339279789,8.91665794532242,15.0012705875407));
#1209=CARTESIAN_POINT('',(-22.6225074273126,8.83045485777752,15.0067314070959));
#1210=CARTESIAN_POINT('',(-22.5892636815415,8.78644133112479,15.0109217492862));
#1211=CARTESIAN_POINT('',(-22.5253295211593,8.69677563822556,15.0226018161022));
#1212=CARTESIAN_POINT('',(-22.4946481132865,8.65111843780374,15.0301026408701));
#1213=CARTESIAN_POINT('',(-22.4361557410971,8.55874922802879,15.0487124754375));
#1214=CARTESIAN_POINT('',(-22.4083439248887,8.51203753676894,15.0598204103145));
#1215=CARTESIAN_POINT('',(-22.329116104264,8.37042191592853,15.0991517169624));
#1216=CARTESIAN_POINT('',(-22.2822311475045,8.27449505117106,15.1333304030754));
#1217=CARTESIAN_POINT('',(-22.2012244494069,8.08511037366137,15.2185048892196));
#1218=CARTESIAN_POINT('',(-22.1670686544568,7.9916466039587,15.269455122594));
#1219=CARTESIAN_POINT('',(-22.1130637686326,7.82031076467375,15.3820272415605));
#1220=CARTESIAN_POINT('',(-22.0921671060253,7.74180009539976,15.4421840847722));
#1221=CARTESIAN_POINT('',(-22.0583316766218,7.59361577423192,15.5745305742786));
#1222=CARTESIAN_POINT('',(-22.0454003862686,7.52395047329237,15.6467314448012));
#1223=CARTESIAN_POINT('',(-22.025441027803,7.39533135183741,15.8019597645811));
#1224=CARTESIAN_POINT('',(-22.0184695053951,7.33648420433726,15.8850824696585));
#1225=CARTESIAN_POINT('',(-22.0085231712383,7.23200811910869,16.059496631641));
#1226=CARTESIAN_POINT('',(-22.0055501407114,7.18638507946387,16.1507917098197));
#1227=CARTESIAN_POINT('',(-22.0016179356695,7.10682882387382,16.3459487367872));
#1228=CARTESIAN_POINT('',(-22.000815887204,7.07394927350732,16.4502428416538));
#1229=CARTESIAN_POINT('',(-22.0000108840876,7.02565261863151,16.662686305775));
#1230=CARTESIAN_POINT('',(-22.0000065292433,7.01020496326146,16.770828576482));
#1231=CARTESIAN_POINT('',(-22.0000014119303,7.00242729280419,16.8994439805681));
#1232=CARTESIAN_POINT('',(-22.0000006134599,7.00151664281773,16.9195571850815));
#1233=CARTESIAN_POINT('',(-21.9999996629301,7.00030375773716,16.9597784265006));
#1234=CARTESIAN_POINT('',(-21.9999995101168,7.00000081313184,16.9798864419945));
#1235=CARTESIAN_POINT('',(-22.,7.,17.));
#1236=B_SPLINE_CURVE_WITH_KNOTS('',3,(#1206,#1207,#1208,#1209,#1210,#1211,#1212,#1213,#1214,
#1215,#1216,#1217,#1218,#1219,#1220,#1221,#1222,#1223,#1224,#1225,#1226,#1227,#1228,#1229,#1230,
#1231,#1232,#1233,#1234,#1235),.UNSPECIFIED.,.F.,.F.,(4,2,2,2,2,2,2,2,2,2,2,2,2,2,4),(0.,
0.165640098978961,0.331426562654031,0.497773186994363,0.664070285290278,0.998329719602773,
1.33168839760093,1.63351885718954,1.93563219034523,2.24058110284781,2.54566581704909,
2.87230570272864,3.19837223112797,3.25877009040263,3.31909739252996),.UNSPECIFIED.);
#1237=EDGE_CURVE('E192',#1129,#1099,#1236,.T.);
#1238=ORIENTED_EDGE('',*,*,#1237,.T.);
#1239=ORIENTED_EDGE('',*,*,#1100,.F.);
#1240=CARTESIAN_POINT('',(-12.,9.,17.));
#1241=DIRECTION('',(-1.,0.,0.));
#1242=DIRECTION('',(0.,0.,1.));
#1243=AXIS2_PLACEMENT_3D('',#1240,#1241,#1242);
#1244=CIRCLE('',#1243,2.);
#1245=EDGE_CURVE('E283',#1139,#1097,#1244,.T.);
#1246=ORIENTED_EDGE('',*,*,#1245,.F.);
#1247=EDGE_LOOP('',(#1205,#1238,#1239,#1246));
#1248=FACE_BOUND('',#1247,.T.);
#1249=ADVANCED_FACE('F285',(#1248),#1204,.F.);
#1250=CARTESIAN_POINT('',(-12.,0.,17.));
#1251=DIRECTION('',(0.,1.,0.));
#1252=DIRECTION('',(-1.,0.,0.));
#1253=AXIS2_PLACEMENT_3D('',#1250,#1251,#1252);
#1254=CYLINDRICAL_SURFACE('',#1253,2.);
#1255=ORIENTED_EDGE('',*,*,#549,.F.);
#1256=ORIENTED_EDGE('',*,*,#1146,.F.);
#1257=CARTESIAN_POINT('',(-12.,9.,17.));
#1258=DIRECTION('',(0.,1.,0.));
#1259=DIRECTION('',(0.,0.,1.));
#1260=AXIS2_PLACEMENT_3D('',#1257,#1258,#1259);
#1261=CIRCLE('',#1260,2.);
#1262=EDGE_CURVE('E509',#1073,#1139,#1261,.T.);
#1263=ORIENTED_EDGE('',*,*,#1262,.F.);
#1264=ORIENTED_EDGE('',*,*,#1074,.F.);
#1265=EDGE_LOOP('',(#1255,#1256,#1263,#1264));
#1266=FACE_BOUND('',#1265,.T.);
#1267=ADVANCED_FACE('F289',(#1266),#1254,.F.);
#1268=CARTESIAN_POINT('',(-12.,9.,17.));
#1269=DIRECTION('',(0.,0.,1.));
#1270=DIRECTION('',(1.,0.,0.));
#1271=AXIS2_PLACEMENT_3D('',#1268,#1269,#1270);
#1272=SPHERICAL_SURFACE('',#1271,2.);
#1273=ORIENTED_EDGE('',*,*,#1262,.T.);
#1274=ORIENTED_EDGE('',*,*,#1245,.T.);
#1275=CARTESIAN_POINT('',(-12.,9.,17.));
#1276=DIRECTION('',(0.,0.,1.));
#1277=DIRECTION('',(1.,0.,0.));
#1278=AXIS2_PLACEMENT_3D('',#1275,#1276,#1277);
#1279=CIRCLE('',#1278,2.);
#1280=EDGE_CURVE('E312',#1073,#1097,#1279,.F.);
#1281=ORIENTED_EDGE('',*,*,#1280,.F.);
#1282=EDGE_LOOP('',(#1273,#1274,#1281));
#1283=FACE_BOUND('',#1282,.T.);
#1284=ADVANCED_FACE('F293',(#1283),#1272,.F.);
#1285=CARTESIAN_POINT('',(-12.,9.,15.));
#1286=DIRECTION('',(0.,0.,-1.));
#1287=DIRECTION('',(-1.,0.,0.));
#1288=AXIS2_PLACEMENT_3D('',#1285,#1286,#1287);
#1289=CYLINDRICAL_SURFACE('',#1288,2.);
#1290=ORIENTED_EDGE('',*,*,#1280,.T.);
#1291=ORIENTED_EDGE('',*,*,#1113,.F.);
#1292=ORIENTED_EDGE('',*,*,#640,.F.);
#1293=ORIENTED_EDGE('',*,*,#1080,.F.);
#1294=EDGE_LOOP('',(#1290,#1291,#1292,#1293));
#1295=FACE_BOUND('',#1294,.T.);
#1296=ADVANCED_FACE('F297',(#1295),#1289,.F.);
#1297=CARTESIAN_POINT('',(-25.,7.,0.));
#1298=DIRECTION('',(0.,0.,1.));
#1299=DIRECTION('',(1.,0.,0.));
#1300=AXIS2_PLACEMENT_3D('',#1297,#1298,#1299);
#1301=CYLINDRICAL_SURFACE('',#1300,3.);
#1302=ORIENTED_EDGE('',*,*,#763,.T.);
#1303=ORIENTED_EDGE('',*,*,#677,.F.);
#1304=EDGE_LOOP('',(#1302,#1303));
#1305=FACE_BOUND('',#1304,.T.);
#1306=ORIENTED_EDGE('',*,*,#610,.T.);
#1307=ORIENTED_EDGE('',*,*,#1106,.F.);
#1308=ORIENTED_EDGE('',*,*,#1237,.F.);
#1309=ORIENTED_EDGE('',*,*,#1132,.T.);
#1310=ORIENTED_EDGE('',*,*,#1193,.F.);
#1311=ORIENTED_EDGE('',*,*,#1051,.F.);
#1312=EDGE_LOOP('',(#1306,#1307,#1308,#1309,#1310,#1311));
#1313=FACE_BOUND('',#1312,.T.);
#1314=ADVANCED_FACE('F269',(#1305,#1313),#1301,.F.);
#1315=CARTESIAN_POINT('',(-15.,-3.,5.));
#1316=DIRECTION('',(0.,0.,1.));
#1317=DIRECTION('',(1.,0.,0.));
#1318=AXIS2_PLACEMENT_3D('',#1315,#1316,#1317);
#1319=PLANE('',#1318);
#1320=ORIENTED_EDGE('',*,*,#149,.T.);
#1321=EDGE_LOOP('',(#1320));
#1322=FACE_BOUND('',#1321,.T.);
#1323=ADVANCED_FACE('F268',(#1322),#1319,.F.);
#1324=CLOSED_SHELL('',(#153,#217,#277,#317,#366,#455,#479,#503,#595,#661,#686,#712,#726,#772,
#792,#804,#824,#844,#864,#884,#904,#924,#944,#964,#984,#996,#1011,#1028,#1038,#1062,#1086,#1117,
#1157,#1199,#1249,#1267,#1284,#1296,#1314,#1323));
#1325=MANIFOLD_SOLID_BREP('B2',#1324);
#1326=ADVANCED_BREP_SHAPE_REPRESENTATION('',(#18,#1325),#14);
#1327=SHAPE_DEFINITION_REPRESENTATION(#9,#1326);
ENDSEC;
END-ISO-10303-21;
